VERSION 5.8 ;
BUSBITCHARS "[]" ;
DIVIDERCHAR "/" ;
UNITS
    DATABASE MICRONS 1000 ;
END UNITS

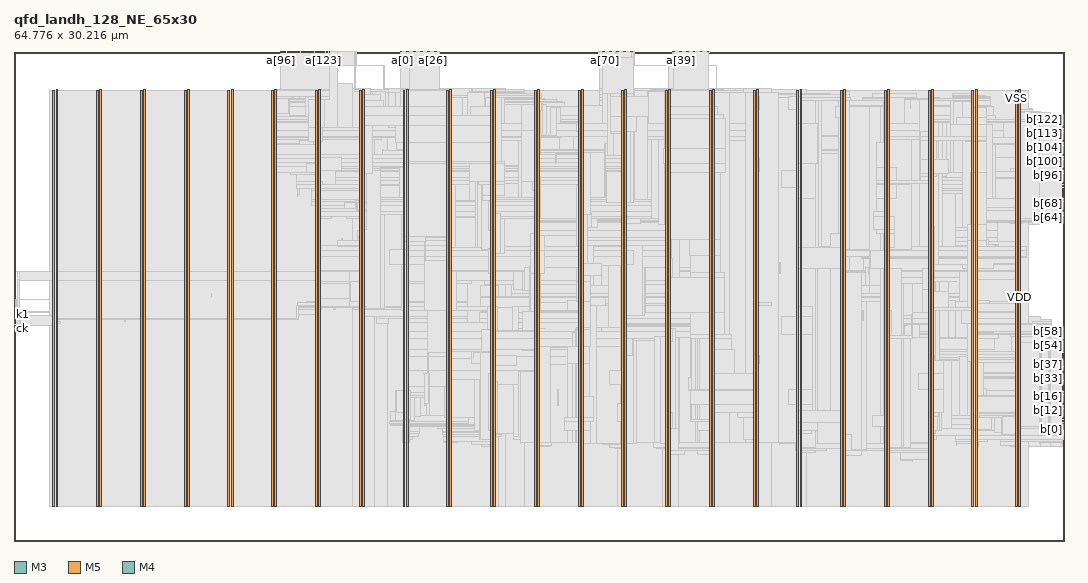
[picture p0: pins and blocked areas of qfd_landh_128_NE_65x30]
MACRO qfd_landh_128_NE_65x30
  FOREIGN qfd_landh_128_NE_65x30 0 0 ;
  CLASS BLOCK ;
  SIZE 64.776 BY 30.216 ;
  PIN a[0]
    DIRECTION INPUT ;
    USE SIGNAL ;
    PORT
      LAYER M3 ;
        RECT  23.94 30.179 23.958 30.216 ;
    END
  END a[0]
  PIN a[100]
    DIRECTION INPUT ;
    USE SIGNAL ;
    PORT
      LAYER M5 ;
        RECT  16.848 30.132 16.872 30.216 ;
    END
  END a[100]
  PIN a[101]
    DIRECTION INPUT ;
    USE SIGNAL ;
    PORT
      LAYER M5 ;
        RECT  16.944 30.132 16.968 30.216 ;
    END
  END a[101]
  PIN a[102]
    DIRECTION INPUT ;
    USE SIGNAL ;
    PORT
      LAYER M5 ;
        RECT  17.04 30.132 17.064 30.216 ;
    END
  END a[102]
  PIN a[103]
    DIRECTION INPUT ;
    USE SIGNAL ;
    PORT
      LAYER M5 ;
        RECT  17.136 30.132 17.16 30.216 ;
    END
  END a[103]
  PIN a[104]
    DIRECTION INPUT ;
    USE SIGNAL ;
    PORT
      LAYER M5 ;
        RECT  17.232 30.132 17.256 30.216 ;
    END
  END a[104]
  PIN a[105]
    DIRECTION INPUT ;
    USE SIGNAL ;
    PORT
      LAYER M5 ;
        RECT  17.328 30.132 17.352 30.216 ;
    END
  END a[105]
  PIN a[106]
    DIRECTION INPUT ;
    USE SIGNAL ;
    PORT
      LAYER M5 ;
        RECT  17.424 30.132 17.448 30.216 ;
    END
  END a[106]
  PIN a[107]
    DIRECTION INPUT ;
    USE SIGNAL ;
    PORT
      LAYER M5 ;
        RECT  17.52 30.132 17.544 30.216 ;
    END
  END a[107]
  PIN a[108]
    DIRECTION INPUT ;
    USE SIGNAL ;
    PORT
      LAYER M5 ;
        RECT  17.616 30.132 17.64 30.216 ;
    END
  END a[108]
  PIN a[109]
    DIRECTION INPUT ;
    USE SIGNAL ;
    PORT
      LAYER M5 ;
        RECT  17.712 30.132 17.736 30.216 ;
    END
  END a[109]
  PIN a[10]
    DIRECTION INPUT ;
    USE SIGNAL ;
    PORT
      LAYER M3 ;
        RECT  24.66 30.179 24.678 30.216 ;
    END
  END a[10]
  PIN a[110]
    DIRECTION INPUT ;
    USE SIGNAL ;
    PORT
      LAYER M5 ;
        RECT  17.808 30.132 17.832 30.216 ;
    END
  END a[110]
  PIN a[111]
    DIRECTION INPUT ;
    USE SIGNAL ;
    PORT
      LAYER M5 ;
        RECT  17.904 30.132 17.928 30.216 ;
    END
  END a[111]
  PIN a[112]
    DIRECTION INPUT ;
    USE SIGNAL ;
    PORT
      LAYER M5 ;
        RECT  18 30.132 18.024 30.216 ;
    END
  END a[112]
  PIN a[113]
    DIRECTION INPUT ;
    USE SIGNAL ;
    PORT
      LAYER M5 ;
        RECT  18.096 30.132 18.12 30.216 ;
    END
  END a[113]
  PIN a[114]
    DIRECTION INPUT ;
    USE SIGNAL ;
    PORT
      LAYER M5 ;
        RECT  18.192 30.132 18.216 30.216 ;
    END
  END a[114]
  PIN a[115]
    DIRECTION INPUT ;
    USE SIGNAL ;
    PORT
      LAYER M5 ;
        RECT  18.288 30.132 18.312 30.216 ;
    END
  END a[115]
  PIN a[116]
    DIRECTION INPUT ;
    USE SIGNAL ;
    PORT
      LAYER M5 ;
        RECT  18.384 30.132 18.408 30.216 ;
    END
  END a[116]
  PIN a[117]
    DIRECTION INPUT ;
    USE SIGNAL ;
    PORT
      LAYER M5 ;
        RECT  18.48 30.132 18.504 30.216 ;
    END
  END a[117]
  PIN a[118]
    DIRECTION INPUT ;
    USE SIGNAL ;
    PORT
      LAYER M5 ;
        RECT  18.576 30.132 18.6 30.216 ;
    END
  END a[118]
  PIN a[119]
    DIRECTION INPUT ;
    USE SIGNAL ;
    PORT
      LAYER M5 ;
        RECT  18.672 30.132 18.696 30.216 ;
    END
  END a[119]
  PIN a[11]
    DIRECTION INPUT ;
    USE SIGNAL ;
    PORT
      LAYER M3 ;
        RECT  24.732 30.179 24.75 30.216 ;
    END
  END a[11]
  PIN a[120]
    DIRECTION INPUT ;
    USE SIGNAL ;
    PORT
      LAYER M5 ;
        RECT  18.768 30.132 18.792 30.216 ;
    END
  END a[120]
  PIN a[121]
    DIRECTION INPUT ;
    USE SIGNAL ;
    PORT
      LAYER M5 ;
        RECT  18.864 30.132 18.888 30.216 ;
    END
  END a[121]
  PIN a[122]
    DIRECTION INPUT ;
    USE SIGNAL ;
    PORT
      LAYER M5 ;
        RECT  18.96 30.132 18.984 30.216 ;
    END
  END a[122]
  PIN a[123]
    DIRECTION INPUT ;
    USE SIGNAL ;
    PORT
      LAYER M5 ;
        RECT  19.056 30.132 19.08 30.216 ;
    END
  END a[123]
  PIN a[124]
    DIRECTION INPUT ;
    USE SIGNAL ;
    PORT
      LAYER M5 ;
        RECT  19.152 30.132 19.176 30.216 ;
    END
  END a[124]
  PIN a[125]
    DIRECTION INPUT ;
    USE SIGNAL ;
    PORT
      LAYER M5 ;
        RECT  19.248 30.132 19.272 30.216 ;
    END
  END a[125]
  PIN a[126]
    DIRECTION INPUT ;
    USE SIGNAL ;
    PORT
      LAYER M5 ;
        RECT  19.344 30.132 19.368 30.216 ;
    END
  END a[126]
  PIN a[127]
    DIRECTION INPUT ;
    USE SIGNAL ;
    PORT
      LAYER M5 ;
        RECT  19.44 30.132 19.464 30.216 ;
    END
  END a[127]
  PIN a[12]
    DIRECTION INPUT ;
    USE SIGNAL ;
    PORT
      LAYER M3 ;
        RECT  24.804 30.179 24.822 30.216 ;
    END
  END a[12]
  PIN a[13]
    DIRECTION INPUT ;
    USE SIGNAL ;
    PORT
      LAYER M3 ;
        RECT  24.876 30.179 24.894 30.216 ;
    END
  END a[13]
  PIN a[14]
    DIRECTION INPUT ;
    USE SIGNAL ;
    PORT
      LAYER M3 ;
        RECT  24.948 30.179 24.966 30.216 ;
    END
  END a[14]
  PIN a[15]
    DIRECTION INPUT ;
    USE SIGNAL ;
    PORT
      LAYER M3 ;
        RECT  25.02 30.179 25.038 30.216 ;
    END
  END a[15]
  PIN a[16]
    DIRECTION INPUT ;
    USE SIGNAL ;
    PORT
      LAYER M3 ;
        RECT  25.092 30.179 25.11 30.216 ;
    END
  END a[16]
  PIN a[17]
    DIRECTION INPUT ;
    USE SIGNAL ;
    PORT
      LAYER M3 ;
        RECT  25.164 30.179 25.182 30.216 ;
    END
  END a[17]
  PIN a[18]
    DIRECTION INPUT ;
    USE SIGNAL ;
    PORT
      LAYER M3 ;
        RECT  25.236 30.179 25.254 30.216 ;
    END
  END a[18]
  PIN a[19]
    DIRECTION INPUT ;
    USE SIGNAL ;
    PORT
      LAYER M3 ;
        RECT  25.308 30.179 25.326 30.216 ;
    END
  END a[19]
  PIN a[1]
    DIRECTION INPUT ;
    USE SIGNAL ;
    PORT
      LAYER M3 ;
        RECT  24.012 30.179 24.03 30.216 ;
    END
  END a[1]
  PIN a[20]
    DIRECTION INPUT ;
    USE SIGNAL ;
    PORT
      LAYER M3 ;
        RECT  25.38 30.179 25.398 30.216 ;
    END
  END a[20]
  PIN a[21]
    DIRECTION INPUT ;
    USE SIGNAL ;
    PORT
      LAYER M3 ;
        RECT  25.452 30.179 25.47 30.216 ;
    END
  END a[21]
  PIN a[22]
    DIRECTION INPUT ;
    USE SIGNAL ;
    PORT
      LAYER M3 ;
        RECT  25.524 30.179 25.542 30.216 ;
    END
  END a[22]
  PIN a[23]
    DIRECTION INPUT ;
    USE SIGNAL ;
    PORT
      LAYER M3 ;
        RECT  25.596 30.179 25.614 30.216 ;
    END
  END a[23]
  PIN a[24]
    DIRECTION INPUT ;
    USE SIGNAL ;
    PORT
      LAYER M3 ;
        RECT  25.668 30.179 25.686 30.216 ;
    END
  END a[24]
  PIN a[25]
    DIRECTION INPUT ;
    USE SIGNAL ;
    PORT
      LAYER M3 ;
        RECT  25.74 30.179 25.758 30.216 ;
    END
  END a[25]
  PIN a[26]
    DIRECTION INPUT ;
    USE SIGNAL ;
    PORT
      LAYER M3 ;
        RECT  25.812 30.179 25.83 30.216 ;
    END
  END a[26]
  PIN a[27]
    DIRECTION INPUT ;
    USE SIGNAL ;
    PORT
      LAYER M3 ;
        RECT  25.884 30.179 25.902 30.216 ;
    END
  END a[27]
  PIN a[28]
    DIRECTION INPUT ;
    USE SIGNAL ;
    PORT
      LAYER M3 ;
        RECT  25.956 30.179 25.974 30.216 ;
    END
  END a[28]
  PIN a[29]
    DIRECTION INPUT ;
    USE SIGNAL ;
    PORT
      LAYER M3 ;
        RECT  26.028 30.179 26.046 30.216 ;
    END
  END a[29]
  PIN a[2]
    DIRECTION INPUT ;
    USE SIGNAL ;
    PORT
      LAYER M3 ;
        RECT  24.084 30.179 24.102 30.216 ;
    END
  END a[2]
  PIN a[30]
    DIRECTION INPUT ;
    USE SIGNAL ;
    PORT
      LAYER M3 ;
        RECT  26.1 30.179 26.118 30.216 ;
    END
  END a[30]
  PIN a[31]
    DIRECTION INPUT ;
    USE SIGNAL ;
    PORT
      LAYER M3 ;
        RECT  26.172 30.179 26.19 30.216 ;
    END
  END a[31]
  PIN a[32]
    DIRECTION INPUT ;
    USE SIGNAL ;
    PORT
      LAYER M3 ;
        RECT  40.644 30.179 40.662 30.216 ;
    END
  END a[32]
  PIN a[33]
    DIRECTION INPUT ;
    USE SIGNAL ;
    PORT
      LAYER M3 ;
        RECT  40.716 30.179 40.734 30.216 ;
    END
  END a[33]
  PIN a[34]
    DIRECTION INPUT ;
    USE SIGNAL ;
    PORT
      LAYER M3 ;
        RECT  40.788 30.179 40.806 30.216 ;
    END
  END a[34]
  PIN a[35]
    DIRECTION INPUT ;
    USE SIGNAL ;
    PORT
      LAYER M3 ;
        RECT  40.86 30.179 40.878 30.216 ;
    END
  END a[35]
  PIN a[36]
    DIRECTION INPUT ;
    USE SIGNAL ;
    PORT
      LAYER M3 ;
        RECT  40.932 30.179 40.95 30.216 ;
    END
  END a[36]
  PIN a[37]
    DIRECTION INPUT ;
    USE SIGNAL ;
    PORT
      LAYER M3 ;
        RECT  41.004 30.179 41.022 30.216 ;
    END
  END a[37]
  PIN a[38]
    DIRECTION INPUT ;
    USE SIGNAL ;
    PORT
      LAYER M3 ;
        RECT  41.076 30.179 41.094 30.216 ;
    END
  END a[38]
  PIN a[39]
    DIRECTION INPUT ;
    USE SIGNAL ;
    PORT
      LAYER M3 ;
        RECT  41.148 30.179 41.166 30.216 ;
    END
  END a[39]
  PIN a[3]
    DIRECTION INPUT ;
    USE SIGNAL ;
    PORT
      LAYER M3 ;
        RECT  24.156 30.179 24.174 30.216 ;
    END
  END a[3]
  PIN a[40]
    DIRECTION INPUT ;
    USE SIGNAL ;
    PORT
      LAYER M3 ;
        RECT  41.22 30.179 41.238 30.216 ;
    END
  END a[40]
  PIN a[41]
    DIRECTION INPUT ;
    USE SIGNAL ;
    PORT
      LAYER M3 ;
        RECT  41.292 30.179 41.31 30.216 ;
    END
  END a[41]
  PIN a[42]
    DIRECTION INPUT ;
    USE SIGNAL ;
    PORT
      LAYER M3 ;
        RECT  41.364 30.179 41.382 30.216 ;
    END
  END a[42]
  PIN a[43]
    DIRECTION INPUT ;
    USE SIGNAL ;
    PORT
      LAYER M3 ;
        RECT  41.436 30.179 41.454 30.216 ;
    END
  END a[43]
  PIN a[44]
    DIRECTION INPUT ;
    USE SIGNAL ;
    PORT
      LAYER M3 ;
        RECT  41.508 30.179 41.526 30.216 ;
    END
  END a[44]
  PIN a[45]
    DIRECTION INPUT ;
    USE SIGNAL ;
    PORT
      LAYER M3 ;
        RECT  41.58 30.179 41.598 30.216 ;
    END
  END a[45]
  PIN a[46]
    DIRECTION INPUT ;
    USE SIGNAL ;
    PORT
      LAYER M3 ;
        RECT  41.652 30.179 41.67 30.216 ;
    END
  END a[46]
  PIN a[47]
    DIRECTION INPUT ;
    USE SIGNAL ;
    PORT
      LAYER M3 ;
        RECT  41.724 30.179 41.742 30.216 ;
    END
  END a[47]
  PIN a[48]
    DIRECTION INPUT ;
    USE SIGNAL ;
    PORT
      LAYER M3 ;
        RECT  41.796 30.179 41.814 30.216 ;
    END
  END a[48]
  PIN a[49]
    DIRECTION INPUT ;
    USE SIGNAL ;
    PORT
      LAYER M3 ;
        RECT  41.868 30.179 41.886 30.216 ;
    END
  END a[49]
  PIN a[4]
    DIRECTION INPUT ;
    USE SIGNAL ;
    PORT
      LAYER M3 ;
        RECT  24.228 30.179 24.246 30.216 ;
    END
  END a[4]
  PIN a[50]
    DIRECTION INPUT ;
    USE SIGNAL ;
    PORT
      LAYER M3 ;
        RECT  41.94 30.179 41.958 30.216 ;
    END
  END a[50]
  PIN a[51]
    DIRECTION INPUT ;
    USE SIGNAL ;
    PORT
      LAYER M3 ;
        RECT  42.012 30.179 42.03 30.216 ;
    END
  END a[51]
  PIN a[52]
    DIRECTION INPUT ;
    USE SIGNAL ;
    PORT
      LAYER M3 ;
        RECT  42.084 30.179 42.102 30.216 ;
    END
  END a[52]
  PIN a[53]
    DIRECTION INPUT ;
    USE SIGNAL ;
    PORT
      LAYER M3 ;
        RECT  42.156 30.179 42.174 30.216 ;
    END
  END a[53]
  PIN a[54]
    DIRECTION INPUT ;
    USE SIGNAL ;
    PORT
      LAYER M3 ;
        RECT  42.228 30.179 42.246 30.216 ;
    END
  END a[54]
  PIN a[55]
    DIRECTION INPUT ;
    USE SIGNAL ;
    PORT
      LAYER M3 ;
        RECT  42.3 30.179 42.318 30.216 ;
    END
  END a[55]
  PIN a[56]
    DIRECTION INPUT ;
    USE SIGNAL ;
    PORT
      LAYER M3 ;
        RECT  42.372 30.179 42.39 30.216 ;
    END
  END a[56]
  PIN a[57]
    DIRECTION INPUT ;
    USE SIGNAL ;
    PORT
      LAYER M3 ;
        RECT  42.444 30.179 42.462 30.216 ;
    END
  END a[57]
  PIN a[58]
    DIRECTION INPUT ;
    USE SIGNAL ;
    PORT
      LAYER M3 ;
        RECT  42.516 30.179 42.534 30.216 ;
    END
  END a[58]
  PIN a[59]
    DIRECTION INPUT ;
    USE SIGNAL ;
    PORT
      LAYER M3 ;
        RECT  42.588 30.179 42.606 30.216 ;
    END
  END a[59]
  PIN a[5]
    DIRECTION INPUT ;
    USE SIGNAL ;
    PORT
      LAYER M3 ;
        RECT  24.3 30.179 24.318 30.216 ;
    END
  END a[5]
  PIN a[60]
    DIRECTION INPUT ;
    USE SIGNAL ;
    PORT
      LAYER M3 ;
        RECT  42.66 30.179 42.678 30.216 ;
    END
  END a[60]
  PIN a[61]
    DIRECTION INPUT ;
    USE SIGNAL ;
    PORT
      LAYER M3 ;
        RECT  42.732 30.179 42.75 30.216 ;
    END
  END a[61]
  PIN a[62]
    DIRECTION INPUT ;
    USE SIGNAL ;
    PORT
      LAYER M3 ;
        RECT  42.804 30.179 42.822 30.216 ;
    END
  END a[62]
  PIN a[63]
    DIRECTION INPUT ;
    USE SIGNAL ;
    PORT
      LAYER M3 ;
        RECT  42.876 30.179 42.894 30.216 ;
    END
  END a[63]
  PIN a[64]
    DIRECTION INPUT ;
    USE SIGNAL ;
    PORT
      LAYER M3 ;
        RECT  36.036 30.179 36.054 30.216 ;
    END
  END a[64]
  PIN a[65]
    DIRECTION INPUT ;
    USE SIGNAL ;
    PORT
      LAYER M3 ;
        RECT  36.108 30.179 36.126 30.216 ;
    END
  END a[65]
  PIN a[66]
    DIRECTION INPUT ;
    USE SIGNAL ;
    PORT
      LAYER M3 ;
        RECT  36.18 30.179 36.198 30.216 ;
    END
  END a[66]
  PIN a[67]
    DIRECTION INPUT ;
    USE SIGNAL ;
    PORT
      LAYER M3 ;
        RECT  36.252 30.179 36.27 30.216 ;
    END
  END a[67]
  PIN a[68]
    DIRECTION INPUT ;
    USE SIGNAL ;
    PORT
      LAYER M3 ;
        RECT  36.324 30.179 36.342 30.216 ;
    END
  END a[68]
  PIN a[69]
    DIRECTION INPUT ;
    USE SIGNAL ;
    PORT
      LAYER M3 ;
        RECT  36.396 30.179 36.414 30.216 ;
    END
  END a[69]
  PIN a[6]
    DIRECTION INPUT ;
    USE SIGNAL ;
    PORT
      LAYER M3 ;
        RECT  24.372 30.179 24.39 30.216 ;
    END
  END a[6]
  PIN a[70]
    DIRECTION INPUT ;
    USE SIGNAL ;
    PORT
      LAYER M3 ;
        RECT  36.468 30.179 36.486 30.216 ;
    END
  END a[70]
  PIN a[71]
    DIRECTION INPUT ;
    USE SIGNAL ;
    PORT
      LAYER M3 ;
        RECT  36.54 30.179 36.558 30.216 ;
    END
  END a[71]
  PIN a[72]
    DIRECTION INPUT ;
    USE SIGNAL ;
    PORT
      LAYER M3 ;
        RECT  36.612 30.179 36.63 30.216 ;
    END
  END a[72]
  PIN a[73]
    DIRECTION INPUT ;
    USE SIGNAL ;
    PORT
      LAYER M3 ;
        RECT  36.684 30.179 36.702 30.216 ;
    END
  END a[73]
  PIN a[74]
    DIRECTION INPUT ;
    USE SIGNAL ;
    PORT
      LAYER M3 ;
        RECT  36.756 30.179 36.774 30.216 ;
    END
  END a[74]
  PIN a[75]
    DIRECTION INPUT ;
    USE SIGNAL ;
    PORT
      LAYER M3 ;
        RECT  36.828 30.179 36.846 30.216 ;
    END
  END a[75]
  PIN a[76]
    DIRECTION INPUT ;
    USE SIGNAL ;
    PORT
      LAYER M3 ;
        RECT  36.9 30.179 36.918 30.216 ;
    END
  END a[76]
  PIN a[77]
    DIRECTION INPUT ;
    USE SIGNAL ;
    PORT
      LAYER M3 ;
        RECT  36.972 30.179 36.99 30.216 ;
    END
  END a[77]
  PIN a[78]
    DIRECTION INPUT ;
    USE SIGNAL ;
    PORT
      LAYER M3 ;
        RECT  37.044 30.179 37.062 30.216 ;
    END
  END a[78]
  PIN a[79]
    DIRECTION INPUT ;
    USE SIGNAL ;
    PORT
      LAYER M3 ;
        RECT  37.116 30.179 37.134 30.216 ;
    END
  END a[79]
  PIN a[7]
    DIRECTION INPUT ;
    USE SIGNAL ;
    PORT
      LAYER M3 ;
        RECT  24.444 30.179 24.462 30.216 ;
    END
  END a[7]
  PIN a[80]
    DIRECTION INPUT ;
    USE SIGNAL ;
    PORT
      LAYER M3 ;
        RECT  37.188 30.179 37.206 30.216 ;
    END
  END a[80]
  PIN a[81]
    DIRECTION INPUT ;
    USE SIGNAL ;
    PORT
      LAYER M3 ;
        RECT  37.26 30.179 37.278 30.216 ;
    END
  END a[81]
  PIN a[82]
    DIRECTION INPUT ;
    USE SIGNAL ;
    PORT
      LAYER M3 ;
        RECT  37.332 30.179 37.35 30.216 ;
    END
  END a[82]
  PIN a[83]
    DIRECTION INPUT ;
    USE SIGNAL ;
    PORT
      LAYER M3 ;
        RECT  37.404 30.179 37.422 30.216 ;
    END
  END a[83]
  PIN a[84]
    DIRECTION INPUT ;
    USE SIGNAL ;
    PORT
      LAYER M3 ;
        RECT  37.476 30.179 37.494 30.216 ;
    END
  END a[84]
  PIN a[85]
    DIRECTION INPUT ;
    USE SIGNAL ;
    PORT
      LAYER M3 ;
        RECT  37.548 30.179 37.566 30.216 ;
    END
  END a[85]
  PIN a[86]
    DIRECTION INPUT ;
    USE SIGNAL ;
    PORT
      LAYER M3 ;
        RECT  37.62 30.179 37.638 30.216 ;
    END
  END a[86]
  PIN a[87]
    DIRECTION INPUT ;
    USE SIGNAL ;
    PORT
      LAYER M3 ;
        RECT  37.692 30.179 37.71 30.216 ;
    END
  END a[87]
  PIN a[88]
    DIRECTION INPUT ;
    USE SIGNAL ;
    PORT
      LAYER M3 ;
        RECT  37.764 30.179 37.782 30.216 ;
    END
  END a[88]
  PIN a[89]
    DIRECTION INPUT ;
    USE SIGNAL ;
    PORT
      LAYER M3 ;
        RECT  37.836 30.179 37.854 30.216 ;
    END
  END a[89]
  PIN a[8]
    DIRECTION INPUT ;
    USE SIGNAL ;
    PORT
      LAYER M3 ;
        RECT  24.516 30.179 24.534 30.216 ;
    END
  END a[8]
  PIN a[90]
    DIRECTION INPUT ;
    USE SIGNAL ;
    PORT
      LAYER M3 ;
        RECT  37.908 30.179 37.926 30.216 ;
    END
  END a[90]
  PIN a[91]
    DIRECTION INPUT ;
    USE SIGNAL ;
    PORT
      LAYER M3 ;
        RECT  37.98 30.179 37.998 30.216 ;
    END
  END a[91]
  PIN a[92]
    DIRECTION INPUT ;
    USE SIGNAL ;
    PORT
      LAYER M3 ;
        RECT  38.052 30.179 38.07 30.216 ;
    END
  END a[92]
  PIN a[93]
    DIRECTION INPUT ;
    USE SIGNAL ;
    PORT
      LAYER M3 ;
        RECT  38.124 30.179 38.142 30.216 ;
    END
  END a[93]
  PIN a[94]
    DIRECTION INPUT ;
    USE SIGNAL ;
    PORT
      LAYER M3 ;
        RECT  38.196 30.179 38.214 30.216 ;
    END
  END a[94]
  PIN a[95]
    DIRECTION INPUT ;
    USE SIGNAL ;
    PORT
      LAYER M3 ;
        RECT  38.268 30.179 38.286 30.216 ;
    END
  END a[95]
  PIN a[96]
    DIRECTION INPUT ;
    USE SIGNAL ;
    PORT
      LAYER M5 ;
        RECT  16.464 30.132 16.488 30.216 ;
    END
  END a[96]
  PIN a[97]
    DIRECTION INPUT ;
    USE SIGNAL ;
    PORT
      LAYER M5 ;
        RECT  16.56 30.132 16.584 30.216 ;
    END
  END a[97]
  PIN a[98]
    DIRECTION INPUT ;
    USE SIGNAL ;
    PORT
      LAYER M5 ;
        RECT  16.656 30.132 16.68 30.216 ;
    END
  END a[98]
  PIN a[99]
    DIRECTION INPUT ;
    USE SIGNAL ;
    PORT
      LAYER M5 ;
        RECT  16.752 30.132 16.776 30.216 ;
    END
  END a[99]
  PIN a[9]
    DIRECTION INPUT ;
    USE SIGNAL ;
    PORT
      LAYER M3 ;
        RECT  24.588 30.179 24.606 30.216 ;
    END
  END a[9]
  PIN b[0]
    DIRECTION OUTPUT ;
    USE SIGNAL ;
    PORT
      LAYER M4 ;
        RECT  64.692 6.864 64.776 6.888 ;
    END
  END b[0]
  PIN b[100]
    DIRECTION OUTPUT ;
    USE SIGNAL ;
    PORT
      LAYER M4 ;
        RECT  64.692 23.376 64.776 23.4 ;
    END
  END b[100]
  PIN b[101]
    DIRECTION OUTPUT ;
    USE SIGNAL ;
    PORT
      LAYER M4 ;
        RECT  64.692 23.472 64.776 23.496 ;
    END
  END b[101]
  PIN b[102]
    DIRECTION OUTPUT ;
    USE SIGNAL ;
    PORT
      LAYER M4 ;
        RECT  64.692 23.568 64.776 23.592 ;
    END
  END b[102]
  PIN b[103]
    DIRECTION OUTPUT ;
    USE SIGNAL ;
    PORT
      LAYER M4 ;
        RECT  64.692 23.664 64.776 23.688 ;
    END
  END b[103]
  PIN b[104]
    DIRECTION OUTPUT ;
    USE SIGNAL ;
    PORT
      LAYER M4 ;
        RECT  64.692 23.76 64.776 23.784 ;
    END
  END b[104]
  PIN b[105]
    DIRECTION OUTPUT ;
    USE SIGNAL ;
    PORT
      LAYER M4 ;
        RECT  64.692 23.856 64.776 23.88 ;
    END
  END b[105]
  PIN b[106]
    DIRECTION OUTPUT ;
    USE SIGNAL ;
    PORT
      LAYER M4 ;
        RECT  64.692 23.952 64.776 23.976 ;
    END
  END b[106]
  PIN b[107]
    DIRECTION OUTPUT ;
    USE SIGNAL ;
    PORT
      LAYER M4 ;
        RECT  64.692 24.048 64.776 24.072 ;
    END
  END b[107]
  PIN b[108]
    DIRECTION OUTPUT ;
    USE SIGNAL ;
    PORT
      LAYER M4 ;
        RECT  64.692 24.144 64.776 24.168 ;
    END
  END b[108]
  PIN b[109]
    DIRECTION OUTPUT ;
    USE SIGNAL ;
    PORT
      LAYER M4 ;
        RECT  64.692 24.24 64.776 24.264 ;
    END
  END b[109]
  PIN b[10]
    DIRECTION OUTPUT ;
    USE SIGNAL ;
    PORT
      LAYER M4 ;
        RECT  64.692 7.824 64.776 7.848 ;
    END
  END b[10]
  PIN b[110]
    DIRECTION OUTPUT ;
    USE SIGNAL ;
    PORT
      LAYER M4 ;
        RECT  64.692 24.336 64.776 24.36 ;
    END
  END b[110]
  PIN b[111]
    DIRECTION OUTPUT ;
    USE SIGNAL ;
    PORT
      LAYER M4 ;
        RECT  64.692 24.432 64.776 24.456 ;
    END
  END b[111]
  PIN b[112]
    DIRECTION OUTPUT ;
    USE SIGNAL ;
    PORT
      LAYER M4 ;
        RECT  64.692 24.528 64.776 24.552 ;
    END
  END b[112]
  PIN b[113]
    DIRECTION OUTPUT ;
    USE SIGNAL ;
    PORT
      LAYER M4 ;
        RECT  64.692 24.624 64.776 24.648 ;
    END
  END b[113]
  PIN b[114]
    DIRECTION OUTPUT ;
    USE SIGNAL ;
    PORT
      LAYER M4 ;
        RECT  64.692 24.72 64.776 24.744 ;
    END
  END b[114]
  PIN b[115]
    DIRECTION OUTPUT ;
    USE SIGNAL ;
    PORT
      LAYER M4 ;
        RECT  64.692 24.816 64.776 24.84 ;
    END
  END b[115]
  PIN b[116]
    DIRECTION OUTPUT ;
    USE SIGNAL ;
    PORT
      LAYER M4 ;
        RECT  64.692 24.912 64.776 24.936 ;
    END
  END b[116]
  PIN b[117]
    DIRECTION OUTPUT ;
    USE SIGNAL ;
    PORT
      LAYER M4 ;
        RECT  64.692 25.008 64.776 25.032 ;
    END
  END b[117]
  PIN b[118]
    DIRECTION OUTPUT ;
    USE SIGNAL ;
    PORT
      LAYER M4 ;
        RECT  64.692 25.104 64.776 25.128 ;
    END
  END b[118]
  PIN b[119]
    DIRECTION OUTPUT ;
    USE SIGNAL ;
    PORT
      LAYER M4 ;
        RECT  64.692 25.2 64.776 25.224 ;
    END
  END b[119]
  PIN b[11]
    DIRECTION OUTPUT ;
    USE SIGNAL ;
    PORT
      LAYER M4 ;
        RECT  64.692 7.92 64.776 7.944 ;
    END
  END b[11]
  PIN b[120]
    DIRECTION OUTPUT ;
    USE SIGNAL ;
    PORT
      LAYER M4 ;
        RECT  64.692 25.296 64.776 25.32 ;
    END
  END b[120]
  PIN b[121]
    DIRECTION OUTPUT ;
    USE SIGNAL ;
    PORT
      LAYER M4 ;
        RECT  64.692 25.392 64.776 25.416 ;
    END
  END b[121]
  PIN b[122]
    DIRECTION OUTPUT ;
    USE SIGNAL ;
    PORT
      LAYER M4 ;
        RECT  64.692 25.488 64.776 25.512 ;
    END
  END b[122]
  PIN b[123]
    DIRECTION OUTPUT ;
    USE SIGNAL ;
    PORT
      LAYER M4 ;
        RECT  64.692 25.584 64.776 25.608 ;
    END
  END b[123]
  PIN b[124]
    DIRECTION OUTPUT ;
    USE SIGNAL ;
    PORT
      LAYER M4 ;
        RECT  64.692 25.68 64.776 25.704 ;
    END
  END b[124]
  PIN b[125]
    DIRECTION OUTPUT ;
    USE SIGNAL ;
    PORT
      LAYER M4 ;
        RECT  64.692 25.776 64.776 25.8 ;
    END
  END b[125]
  PIN b[126]
    DIRECTION OUTPUT ;
    USE SIGNAL ;
    PORT
      LAYER M4 ;
        RECT  64.692 25.872 64.776 25.896 ;
    END
  END b[126]
  PIN b[127]
    DIRECTION OUTPUT ;
    USE SIGNAL ;
    PORT
      LAYER M4 ;
        RECT  64.692 25.968 64.776 25.992 ;
    END
  END b[127]
  PIN b[12]
    DIRECTION OUTPUT ;
    USE SIGNAL ;
    PORT
      LAYER M4 ;
        RECT  64.692 8.016 64.776 8.04 ;
    END
  END b[12]
  PIN b[13]
    DIRECTION OUTPUT ;
    USE SIGNAL ;
    PORT
      LAYER M4 ;
        RECT  64.692 8.112 64.776 8.136 ;
    END
  END b[13]
  PIN b[14]
    DIRECTION OUTPUT ;
    USE SIGNAL ;
    PORT
      LAYER M4 ;
        RECT  64.692 8.208 64.776 8.232 ;
    END
  END b[14]
  PIN b[15]
    DIRECTION OUTPUT ;
    USE SIGNAL ;
    PORT
      LAYER M4 ;
        RECT  64.692 8.304 64.776 8.328 ;
    END
  END b[15]
  PIN b[16]
    DIRECTION OUTPUT ;
    USE SIGNAL ;
    PORT
      LAYER M4 ;
        RECT  64.692 8.4 64.776 8.424 ;
    END
  END b[16]
  PIN b[17]
    DIRECTION OUTPUT ;
    USE SIGNAL ;
    PORT
      LAYER M4 ;
        RECT  64.692 8.496 64.776 8.52 ;
    END
  END b[17]
  PIN b[18]
    DIRECTION OUTPUT ;
    USE SIGNAL ;
    PORT
      LAYER M4 ;
        RECT  64.692 8.592 64.776 8.616 ;
    END
  END b[18]
  PIN b[19]
    DIRECTION OUTPUT ;
    USE SIGNAL ;
    PORT
      LAYER M4 ;
        RECT  64.692 8.688 64.776 8.712 ;
    END
  END b[19]
  PIN b[1]
    DIRECTION OUTPUT ;
    USE SIGNAL ;
    PORT
      LAYER M4 ;
        RECT  64.692 6.96 64.776 6.984 ;
    END
  END b[1]
  PIN b[20]
    DIRECTION OUTPUT ;
    USE SIGNAL ;
    PORT
      LAYER M4 ;
        RECT  64.692 8.784 64.776 8.808 ;
    END
  END b[20]
  PIN b[21]
    DIRECTION OUTPUT ;
    USE SIGNAL ;
    PORT
      LAYER M4 ;
        RECT  64.692 8.88 64.776 8.904 ;
    END
  END b[21]
  PIN b[22]
    DIRECTION OUTPUT ;
    USE SIGNAL ;
    PORT
      LAYER M4 ;
        RECT  64.692 8.976 64.776 9 ;
    END
  END b[22]
  PIN b[23]
    DIRECTION OUTPUT ;
    USE SIGNAL ;
    PORT
      LAYER M4 ;
        RECT  64.692 9.072 64.776 9.096 ;
    END
  END b[23]
  PIN b[24]
    DIRECTION OUTPUT ;
    USE SIGNAL ;
    PORT
      LAYER M4 ;
        RECT  64.692 9.168 64.776 9.192 ;
    END
  END b[24]
  PIN b[25]
    DIRECTION OUTPUT ;
    USE SIGNAL ;
    PORT
      LAYER M4 ;
        RECT  64.692 9.264 64.776 9.288 ;
    END
  END b[25]
  PIN b[26]
    DIRECTION OUTPUT ;
    USE SIGNAL ;
    PORT
      LAYER M4 ;
        RECT  64.692 9.36 64.776 9.384 ;
    END
  END b[26]
  PIN b[27]
    DIRECTION OUTPUT ;
    USE SIGNAL ;
    PORT
      LAYER M4 ;
        RECT  64.692 9.456 64.776 9.48 ;
    END
  END b[27]
  PIN b[28]
    DIRECTION OUTPUT ;
    USE SIGNAL ;
    PORT
      LAYER M4 ;
        RECT  64.692 9.552 64.776 9.576 ;
    END
  END b[28]
  PIN b[29]
    DIRECTION OUTPUT ;
    USE SIGNAL ;
    PORT
      LAYER M4 ;
        RECT  64.692 9.648 64.776 9.672 ;
    END
  END b[29]
  PIN b[2]
    DIRECTION OUTPUT ;
    USE SIGNAL ;
    PORT
      LAYER M4 ;
        RECT  64.692 7.056 64.776 7.08 ;
    END
  END b[2]
  PIN b[30]
    DIRECTION OUTPUT ;
    USE SIGNAL ;
    PORT
      LAYER M4 ;
        RECT  64.692 9.744 64.776 9.768 ;
    END
  END b[30]
  PIN b[31]
    DIRECTION OUTPUT ;
    USE SIGNAL ;
    PORT
      LAYER M4 ;
        RECT  64.692 9.84 64.776 9.864 ;
    END
  END b[31]
  PIN b[32]
    DIRECTION OUTPUT ;
    USE SIGNAL ;
    PORT
      LAYER M4 ;
        RECT  64.692 9.936 64.776 9.96 ;
    END
  END b[32]
  PIN b[33]
    DIRECTION OUTPUT ;
    USE SIGNAL ;
    PORT
      LAYER M4 ;
        RECT  64.692 10.032 64.776 10.056 ;
    END
  END b[33]
  PIN b[34]
    DIRECTION OUTPUT ;
    USE SIGNAL ;
    PORT
      LAYER M4 ;
        RECT  64.692 10.128 64.776 10.152 ;
    END
  END b[34]
  PIN b[35]
    DIRECTION OUTPUT ;
    USE SIGNAL ;
    PORT
      LAYER M4 ;
        RECT  64.692 10.224 64.776 10.248 ;
    END
  END b[35]
  PIN b[36]
    DIRECTION OUTPUT ;
    USE SIGNAL ;
    PORT
      LAYER M4 ;
        RECT  64.692 10.32 64.776 10.344 ;
    END
  END b[36]
  PIN b[37]
    DIRECTION OUTPUT ;
    USE SIGNAL ;
    PORT
      LAYER M4 ;
        RECT  64.692 10.416 64.776 10.44 ;
    END
  END b[37]
  PIN b[38]
    DIRECTION OUTPUT ;
    USE SIGNAL ;
    PORT
      LAYER M4 ;
        RECT  64.692 10.512 64.776 10.536 ;
    END
  END b[38]
  PIN b[39]
    DIRECTION OUTPUT ;
    USE SIGNAL ;
    PORT
      LAYER M4 ;
        RECT  64.692 10.608 64.776 10.632 ;
    END
  END b[39]
  PIN b[3]
    DIRECTION OUTPUT ;
    USE SIGNAL ;
    PORT
      LAYER M4 ;
        RECT  64.692 7.152 64.776 7.176 ;
    END
  END b[3]
  PIN b[40]
    DIRECTION OUTPUT ;
    USE SIGNAL ;
    PORT
      LAYER M4 ;
        RECT  64.692 10.704 64.776 10.728 ;
    END
  END b[40]
  PIN b[41]
    DIRECTION OUTPUT ;
    USE SIGNAL ;
    PORT
      LAYER M4 ;
        RECT  64.692 10.8 64.776 10.824 ;
    END
  END b[41]
  PIN b[42]
    DIRECTION OUTPUT ;
    USE SIGNAL ;
    PORT
      LAYER M4 ;
        RECT  64.692 10.896 64.776 10.92 ;
    END
  END b[42]
  PIN b[43]
    DIRECTION OUTPUT ;
    USE SIGNAL ;
    PORT
      LAYER M4 ;
        RECT  64.692 10.992 64.776 11.016 ;
    END
  END b[43]
  PIN b[44]
    DIRECTION OUTPUT ;
    USE SIGNAL ;
    PORT
      LAYER M4 ;
        RECT  64.692 11.088 64.776 11.112 ;
    END
  END b[44]
  PIN b[45]
    DIRECTION OUTPUT ;
    USE SIGNAL ;
    PORT
      LAYER M4 ;
        RECT  64.692 11.184 64.776 11.208 ;
    END
  END b[45]
  PIN b[46]
    DIRECTION OUTPUT ;
    USE SIGNAL ;
    PORT
      LAYER M4 ;
        RECT  64.692 11.28 64.776 11.304 ;
    END
  END b[46]
  PIN b[47]
    DIRECTION OUTPUT ;
    USE SIGNAL ;
    PORT
      LAYER M4 ;
        RECT  64.692 11.376 64.776 11.4 ;
    END
  END b[47]
  PIN b[48]
    DIRECTION OUTPUT ;
    USE SIGNAL ;
    PORT
      LAYER M4 ;
        RECT  64.692 11.472 64.776 11.496 ;
    END
  END b[48]
  PIN b[49]
    DIRECTION OUTPUT ;
    USE SIGNAL ;
    PORT
      LAYER M4 ;
        RECT  64.692 11.568 64.776 11.592 ;
    END
  END b[49]
  PIN b[4]
    DIRECTION OUTPUT ;
    USE SIGNAL ;
    PORT
      LAYER M4 ;
        RECT  64.692 7.248 64.776 7.272 ;
    END
  END b[4]
  PIN b[50]
    DIRECTION OUTPUT ;
    USE SIGNAL ;
    PORT
      LAYER M4 ;
        RECT  64.692 11.664 64.776 11.688 ;
    END
  END b[50]
  PIN b[51]
    DIRECTION OUTPUT ;
    USE SIGNAL ;
    PORT
      LAYER M4 ;
        RECT  64.692 11.76 64.776 11.784 ;
    END
  END b[51]
  PIN b[52]
    DIRECTION OUTPUT ;
    USE SIGNAL ;
    PORT
      LAYER M4 ;
        RECT  64.692 11.856 64.776 11.88 ;
    END
  END b[52]
  PIN b[53]
    DIRECTION OUTPUT ;
    USE SIGNAL ;
    PORT
      LAYER M4 ;
        RECT  64.692 11.952 64.776 11.976 ;
    END
  END b[53]
  PIN b[54]
    DIRECTION OUTPUT ;
    USE SIGNAL ;
    PORT
      LAYER M4 ;
        RECT  64.692 12.048 64.776 12.072 ;
    END
  END b[54]
  PIN b[55]
    DIRECTION OUTPUT ;
    USE SIGNAL ;
    PORT
      LAYER M4 ;
        RECT  64.692 12.144 64.776 12.168 ;
    END
  END b[55]
  PIN b[56]
    DIRECTION OUTPUT ;
    USE SIGNAL ;
    PORT
      LAYER M4 ;
        RECT  64.692 12.24 64.776 12.264 ;
    END
  END b[56]
  PIN b[57]
    DIRECTION OUTPUT ;
    USE SIGNAL ;
    PORT
      LAYER M4 ;
        RECT  64.692 12.336 64.776 12.36 ;
    END
  END b[57]
  PIN b[58]
    DIRECTION OUTPUT ;
    USE SIGNAL ;
    PORT
      LAYER M4 ;
        RECT  64.692 12.432 64.776 12.456 ;
    END
  END b[58]
  PIN b[59]
    DIRECTION OUTPUT ;
    USE SIGNAL ;
    PORT
      LAYER M4 ;
        RECT  64.692 12.528 64.776 12.552 ;
    END
  END b[59]
  PIN b[5]
    DIRECTION OUTPUT ;
    USE SIGNAL ;
    PORT
      LAYER M4 ;
        RECT  64.692 7.344 64.776 7.368 ;
    END
  END b[5]
  PIN b[60]
    DIRECTION OUTPUT ;
    USE SIGNAL ;
    PORT
      LAYER M4 ;
        RECT  64.692 12.624 64.776 12.648 ;
    END
  END b[60]
  PIN b[61]
    DIRECTION OUTPUT ;
    USE SIGNAL ;
    PORT
      LAYER M4 ;
        RECT  64.692 12.72 64.776 12.744 ;
    END
  END b[61]
  PIN b[62]
    DIRECTION OUTPUT ;
    USE SIGNAL ;
    PORT
      LAYER M4 ;
        RECT  64.692 12.816 64.776 12.84 ;
    END
  END b[62]
  PIN b[63]
    DIRECTION OUTPUT ;
    USE SIGNAL ;
    PORT
      LAYER M4 ;
        RECT  64.692 12.912 64.776 12.936 ;
    END
  END b[63]
  PIN b[64]
    DIRECTION OUTPUT ;
    USE SIGNAL ;
    PORT
      LAYER M4 ;
        RECT  64.692 19.92 64.776 19.944 ;
    END
  END b[64]
  PIN b[65]
    DIRECTION OUTPUT ;
    USE SIGNAL ;
    PORT
      LAYER M4 ;
        RECT  64.692 20.016 64.776 20.04 ;
    END
  END b[65]
  PIN b[66]
    DIRECTION OUTPUT ;
    USE SIGNAL ;
    PORT
      LAYER M4 ;
        RECT  64.692 20.112 64.776 20.136 ;
    END
  END b[66]
  PIN b[67]
    DIRECTION OUTPUT ;
    USE SIGNAL ;
    PORT
      LAYER M4 ;
        RECT  64.692 20.208 64.776 20.232 ;
    END
  END b[67]
  PIN b[68]
    DIRECTION OUTPUT ;
    USE SIGNAL ;
    PORT
      LAYER M4 ;
        RECT  64.692 20.304 64.776 20.328 ;
    END
  END b[68]
  PIN b[69]
    DIRECTION OUTPUT ;
    USE SIGNAL ;
    PORT
      LAYER M4 ;
        RECT  64.692 20.4 64.776 20.424 ;
    END
  END b[69]
  PIN b[6]
    DIRECTION OUTPUT ;
    USE SIGNAL ;
    PORT
      LAYER M4 ;
        RECT  64.692 7.44 64.776 7.464 ;
    END
  END b[6]
  PIN b[70]
    DIRECTION OUTPUT ;
    USE SIGNAL ;
    PORT
      LAYER M4 ;
        RECT  64.692 20.496 64.776 20.52 ;
    END
  END b[70]
  PIN b[71]
    DIRECTION OUTPUT ;
    USE SIGNAL ;
    PORT
      LAYER M4 ;
        RECT  64.692 20.592 64.776 20.616 ;
    END
  END b[71]
  PIN b[72]
    DIRECTION OUTPUT ;
    USE SIGNAL ;
    PORT
      LAYER M4 ;
        RECT  64.692 20.688 64.776 20.712 ;
    END
  END b[72]
  PIN b[73]
    DIRECTION OUTPUT ;
    USE SIGNAL ;
    PORT
      LAYER M4 ;
        RECT  64.692 20.784 64.776 20.808 ;
    END
  END b[73]
  PIN b[74]
    DIRECTION OUTPUT ;
    USE SIGNAL ;
    PORT
      LAYER M4 ;
        RECT  64.692 20.88 64.776 20.904 ;
    END
  END b[74]
  PIN b[75]
    DIRECTION OUTPUT ;
    USE SIGNAL ;
    PORT
      LAYER M4 ;
        RECT  64.692 20.976 64.776 21 ;
    END
  END b[75]
  PIN b[76]
    DIRECTION OUTPUT ;
    USE SIGNAL ;
    PORT
      LAYER M4 ;
        RECT  64.692 21.072 64.776 21.096 ;
    END
  END b[76]
  PIN b[77]
    DIRECTION OUTPUT ;
    USE SIGNAL ;
    PORT
      LAYER M4 ;
        RECT  64.692 21.168 64.776 21.192 ;
    END
  END b[77]
  PIN b[78]
    DIRECTION OUTPUT ;
    USE SIGNAL ;
    PORT
      LAYER M4 ;
        RECT  64.692 21.264 64.776 21.288 ;
    END
  END b[78]
  PIN b[79]
    DIRECTION OUTPUT ;
    USE SIGNAL ;
    PORT
      LAYER M4 ;
        RECT  64.692 21.36 64.776 21.384 ;
    END
  END b[79]
  PIN b[7]
    DIRECTION OUTPUT ;
    USE SIGNAL ;
    PORT
      LAYER M4 ;
        RECT  64.692 7.536 64.776 7.56 ;
    END
  END b[7]
  PIN b[80]
    DIRECTION OUTPUT ;
    USE SIGNAL ;
    PORT
      LAYER M4 ;
        RECT  64.692 21.456 64.776 21.48 ;
    END
  END b[80]
  PIN b[81]
    DIRECTION OUTPUT ;
    USE SIGNAL ;
    PORT
      LAYER M4 ;
        RECT  64.692 21.552 64.776 21.576 ;
    END
  END b[81]
  PIN b[82]
    DIRECTION OUTPUT ;
    USE SIGNAL ;
    PORT
      LAYER M4 ;
        RECT  64.692 21.648 64.776 21.672 ;
    END
  END b[82]
  PIN b[83]
    DIRECTION OUTPUT ;
    USE SIGNAL ;
    PORT
      LAYER M4 ;
        RECT  64.692 21.744 64.776 21.768 ;
    END
  END b[83]
  PIN b[84]
    DIRECTION OUTPUT ;
    USE SIGNAL ;
    PORT
      LAYER M4 ;
        RECT  64.692 21.84 64.776 21.864 ;
    END
  END b[84]
  PIN b[85]
    DIRECTION OUTPUT ;
    USE SIGNAL ;
    PORT
      LAYER M4 ;
        RECT  64.692 21.936 64.776 21.96 ;
    END
  END b[85]
  PIN b[86]
    DIRECTION OUTPUT ;
    USE SIGNAL ;
    PORT
      LAYER M4 ;
        RECT  64.692 22.032 64.776 22.056 ;
    END
  END b[86]
  PIN b[87]
    DIRECTION OUTPUT ;
    USE SIGNAL ;
    PORT
      LAYER M4 ;
        RECT  64.692 22.128 64.776 22.152 ;
    END
  END b[87]
  PIN b[88]
    DIRECTION OUTPUT ;
    USE SIGNAL ;
    PORT
      LAYER M4 ;
        RECT  64.692 22.224 64.776 22.248 ;
    END
  END b[88]
  PIN b[89]
    DIRECTION OUTPUT ;
    USE SIGNAL ;
    PORT
      LAYER M4 ;
        RECT  64.692 22.32 64.776 22.344 ;
    END
  END b[89]
  PIN b[8]
    DIRECTION OUTPUT ;
    USE SIGNAL ;
    PORT
      LAYER M4 ;
        RECT  64.692 7.632 64.776 7.656 ;
    END
  END b[8]
  PIN b[90]
    DIRECTION OUTPUT ;
    USE SIGNAL ;
    PORT
      LAYER M4 ;
        RECT  64.692 22.416 64.776 22.44 ;
    END
  END b[90]
  PIN b[91]
    DIRECTION OUTPUT ;
    USE SIGNAL ;
    PORT
      LAYER M4 ;
        RECT  64.692 22.512 64.776 22.536 ;
    END
  END b[91]
  PIN b[92]
    DIRECTION OUTPUT ;
    USE SIGNAL ;
    PORT
      LAYER M4 ;
        RECT  64.692 22.608 64.776 22.632 ;
    END
  END b[92]
  PIN b[93]
    DIRECTION OUTPUT ;
    USE SIGNAL ;
    PORT
      LAYER M4 ;
        RECT  64.692 22.704 64.776 22.728 ;
    END
  END b[93]
  PIN b[94]
    DIRECTION OUTPUT ;
    USE SIGNAL ;
    PORT
      LAYER M4 ;
        RECT  64.692 22.8 64.776 22.824 ;
    END
  END b[94]
  PIN b[95]
    DIRECTION OUTPUT ;
    USE SIGNAL ;
    PORT
      LAYER M4 ;
        RECT  64.692 22.896 64.776 22.92 ;
    END
  END b[95]
  PIN b[96]
    DIRECTION OUTPUT ;
    USE SIGNAL ;
    PORT
      LAYER M4 ;
        RECT  64.692 22.992 64.776 23.016 ;
    END
  END b[96]
  PIN b[97]
    DIRECTION OUTPUT ;
    USE SIGNAL ;
    PORT
      LAYER M4 ;
        RECT  64.692 23.088 64.776 23.112 ;
    END
  END b[97]
  PIN b[98]
    DIRECTION OUTPUT ;
    USE SIGNAL ;
    PORT
      LAYER M4 ;
        RECT  64.692 23.184 64.776 23.208 ;
    END
  END b[98]
  PIN b[99]
    DIRECTION OUTPUT ;
    USE SIGNAL ;
    PORT
      LAYER M4 ;
        RECT  64.692 23.28 64.776 23.304 ;
    END
  END b[99]
  PIN b[9]
    DIRECTION OUTPUT ;
    USE SIGNAL ;
    PORT
      LAYER M4 ;
        RECT  64.692 7.728 64.776 7.752 ;
    END
  END b[9]
  PIN ck
    DIRECTION INPUT ;
    USE SIGNAL ;
    PORT
      LAYER M4 ;
        RECT  0 13.104 0.084 13.128 ;
    END
  END ck
  PIN ckf
    DIRECTION INPUT ;
    USE SIGNAL ;
    PORT
      LAYER M4 ;
        RECT  0 13.2 0.084 13.224 ;
    END
  END ckf
  PIN ea
    DIRECTION INPUT ;
    USE SIGNAL ;
    PORT
      LAYER M3 ;
        RECT  23.868 30.179 23.886 30.216 ;
    END
  END ea
  PIN fault
    DIRECTION OUTPUT ;
    USE SIGNAL ;
    PORT
      LAYER M4 ;
        RECT  0 13.296 0.084 13.32 ;
    END
  END fault
  PIN k0
    DIRECTION INPUT ;
    USE SIGNAL ;
    PORT
      LAYER M4 ;
        RECT  0 13.392 0.084 13.416 ;
    END
  END k0
  PIN k1
    DIRECTION INPUT ;
    USE SIGNAL ;
    PORT
      LAYER M4 ;
        RECT  0 13.488 0.084 13.512 ;
    END
  END k1
  PIN k2
    DIRECTION INPUT ;
    USE SIGNAL ;
    PORT
      LAYER M4 ;
        RECT  0 13.584 0.084 13.608 ;
    END
  END k2
  PIN rs
    DIRECTION INPUT ;
    USE SIGNAL ;
    PORT
      LAYER M4 ;
        RECT  0 13.68 0.084 13.704 ;
    END
  END rs
  PIN tie_hi
    DIRECTION OUTPUT ;
    USE SIGNAL ;
    PORT
      LAYER M4 ;
        RECT  0 13.776 0.084 13.8 ;
    END
  END tie_hi
  PIN tie_lo
    DIRECTION OUTPUT ;
    USE SIGNAL ;
    PORT
      LAYER M4 ;
        RECT  0 13.872 0.084 13.896 ;
    END
  END tie_lo
  PIN VDD
    DIRECTION INOUT ;
    USE POWER ;
    PORT
      LAYER M5 ;
        RECT  61.992 2.151 62.112 27.833 ;
        RECT  59.292 2.151 59.412 27.833 ;
        RECT  56.592 2.151 56.712 27.833 ;
        RECT  53.892 2.151 54.012 27.833 ;
        RECT  51.192 2.151 51.312 27.833 ;
        RECT  48.492 2.151 48.612 27.833 ;
        RECT  45.792 2.151 45.912 27.833 ;
        RECT  43.092 2.151 43.212 27.833 ;
        RECT  40.392 2.151 40.512 27.833 ;
        RECT  37.692 2.151 37.812 27.833 ;
        RECT  34.992 2.151 35.112 27.833 ;
        RECT  32.292 2.151 32.412 27.833 ;
        RECT  29.592 2.151 29.712 27.833 ;
        RECT  26.892 2.151 27.012 27.833 ;
        RECT  24.192 2.151 24.312 27.833 ;
        RECT  21.492 2.151 21.612 27.833 ;
        RECT  18.792 2.151 18.912 27.833 ;
        RECT  16.092 2.151 16.212 27.833 ;
        RECT  13.392 2.151 13.512 27.833 ;
        RECT  10.692 2.151 10.812 27.833 ;
        RECT  7.992 2.151 8.112 27.833 ;
        RECT  5.292 2.151 5.412 27.833 ;
        RECT  2.592 2.151 2.712 27.833 ;
    END
  END VDD
  PIN VSS
    DIRECTION INOUT ;
    USE GROUND ;
    PORT
      LAYER M5 ;
        RECT  61.8 2.137 61.92 27.819 ;
        RECT  59.1 2.137 59.22 27.819 ;
        RECT  56.4 2.137 56.52 27.819 ;
        RECT  53.7 2.137 53.82 27.819 ;
        RECT  51 2.137 51.12 27.819 ;
        RECT  48.3 2.137 48.42 27.819 ;
        RECT  45.6 2.137 45.72 27.819 ;
        RECT  42.9 2.137 43.02 27.819 ;
        RECT  40.2 2.137 40.32 27.819 ;
        RECT  37.5 2.137 37.62 27.819 ;
        RECT  34.8 2.137 34.92 27.819 ;
        RECT  32.1 2.137 32.22 27.819 ;
        RECT  29.4 2.137 29.52 27.819 ;
        RECT  26.7 2.137 26.82 27.819 ;
        RECT  24 2.137 24.12 27.819 ;
        RECT  21.3 2.137 21.42 27.819 ;
        RECT  18.6 2.137 18.72 27.819 ;
        RECT  15.9 2.137 16.02 27.819 ;
        RECT  13.2 2.137 13.32 27.819 ;
        RECT  10.5 2.137 10.62 27.819 ;
        RECT  7.8 2.137 7.92 27.819 ;
        RECT  5.1 2.137 5.22 27.819 ;
        RECT  2.4 2.137 2.52 27.819 ;
    END
  END VSS
  OBS
    LAYER RVTN ;
     RECT  2.16 2.16 62.586 2.295 ;
     RECT  2.16 2.565 62.586 2.835 ;
     RECT  2.16 3.105 62.586 3.375 ;
     RECT  2.16 3.645 62.586 3.915 ;
     RECT  2.16 4.185 62.586 4.455 ;
     RECT  2.16 4.725 62.586 4.995 ;
     RECT  2.16 5.265 62.586 5.535 ;
     RECT  2.16 5.805 62.586 6.075 ;
     RECT  2.16 6.345 62.586 6.615 ;
     RECT  2.16 6.885 62.586 7.155 ;
     RECT  2.16 7.425 62.586 7.695 ;
     RECT  2.16 7.965 62.586 8.235 ;
     RECT  2.16 8.505 62.586 8.775 ;
     RECT  2.16 9.045 62.586 9.315 ;
     RECT  2.16 9.585 62.586 9.855 ;
     RECT  2.16 10.125 62.586 10.395 ;
     RECT  2.16 10.665 62.586 10.935 ;
     RECT  2.16 11.205 62.586 11.475 ;
     RECT  2.16 11.745 62.586 12.015 ;
     RECT  2.16 12.285 62.586 12.555 ;
     RECT  2.16 12.825 62.586 13.095 ;
     RECT  2.16 13.365 62.586 13.635 ;
     RECT  2.16 13.905 62.586 14.175 ;
     RECT  2.16 14.445 62.586 14.715 ;
     RECT  2.16 14.985 62.586 15.255 ;
     RECT  2.16 15.525 62.586 15.795 ;
     RECT  2.16 16.065 62.586 16.335 ;
     RECT  2.16 16.605 62.586 16.875 ;
     RECT  2.16 17.145 62.586 17.415 ;
     RECT  2.16 17.685 62.586 17.955 ;
     RECT  2.16 18.225 62.586 18.495 ;
     RECT  2.16 18.765 62.586 19.035 ;
     RECT  2.16 19.305 62.586 19.575 ;
     RECT  2.16 19.845 62.586 20.115 ;
     RECT  2.16 20.385 62.586 20.655 ;
     RECT  2.16 20.925 62.586 21.195 ;
     RECT  2.16 21.465 62.586 21.735 ;
     RECT  2.16 22.005 62.586 22.275 ;
     RECT  2.16 22.545 62.586 22.815 ;
     RECT  2.16 23.085 62.586 23.355 ;
     RECT  2.16 23.625 62.586 23.895 ;
     RECT  2.16 24.165 62.586 24.435 ;
     RECT  2.16 24.705 62.586 24.975 ;
     RECT  2.16 25.245 62.586 25.515 ;
     RECT  2.16 25.785 62.586 26.055 ;
     RECT  2.16 26.325 62.586 26.595 ;
     RECT  2.16 26.865 62.586 27.135 ;
     RECT  2.16 27.405 62.586 27.675 ;
    LAYER RVTP ;
     RECT  2.16 2.295 62.586 2.565 ;
     RECT  2.16 2.835 62.586 3.105 ;
     RECT  2.16 3.375 62.586 3.645 ;
     RECT  2.16 3.915 62.586 4.185 ;
     RECT  2.16 4.455 62.586 4.725 ;
     RECT  2.16 4.995 62.586 5.265 ;
     RECT  2.16 5.535 62.586 5.805 ;
     RECT  2.16 6.075 62.586 6.345 ;
     RECT  2.16 6.615 62.586 6.885 ;
     RECT  2.16 7.155 62.586 7.425 ;
     RECT  2.16 7.695 62.586 7.965 ;
     RECT  2.16 8.235 62.586 8.505 ;
     RECT  2.16 8.775 62.586 9.045 ;
     RECT  2.16 9.315 62.586 9.585 ;
     RECT  2.16 9.855 62.586 10.125 ;
     RECT  2.16 10.395 62.586 10.665 ;
     RECT  2.16 10.935 62.586 11.205 ;
     RECT  2.16 11.475 62.586 11.745 ;
     RECT  2.16 12.015 62.586 12.285 ;
     RECT  2.16 12.555 62.586 12.825 ;
     RECT  2.16 13.095 62.586 13.365 ;
     RECT  2.16 13.635 62.586 13.905 ;
     RECT  2.16 14.175 62.586 14.445 ;
     RECT  2.16 14.715 62.586 14.985 ;
     RECT  2.16 15.255 62.586 15.525 ;
     RECT  2.16 15.795 62.586 16.065 ;
     RECT  2.16 16.335 62.586 16.605 ;
     RECT  2.16 16.875 62.586 17.145 ;
     RECT  2.16 17.415 62.586 17.685 ;
     RECT  2.16 17.955 62.586 18.225 ;
     RECT  2.16 18.495 62.586 18.765 ;
     RECT  2.16 19.035 62.586 19.305 ;
     RECT  2.16 19.575 62.586 19.845 ;
     RECT  2.16 20.115 62.586 20.385 ;
     RECT  2.16 20.655 62.586 20.925 ;
     RECT  2.16 21.195 62.586 21.465 ;
     RECT  2.16 21.735 62.586 22.005 ;
     RECT  2.16 22.275 62.586 22.545 ;
     RECT  2.16 22.815 62.586 23.085 ;
     RECT  2.16 23.355 62.586 23.625 ;
     RECT  2.16 23.895 62.586 24.165 ;
     RECT  2.16 24.435 62.586 24.705 ;
     RECT  2.16 24.975 62.586 25.245 ;
     RECT  2.16 25.515 62.586 25.785 ;
     RECT  2.16 26.055 62.586 26.325 ;
     RECT  2.16 26.595 62.586 26.865 ;
     RECT  2.16 27.135 62.586 27.405 ;
     RECT  2.16 27.675 62.586 27.81 ;
    LAYER M1 ;
     RECT  2.16 2.151 62.586 27.819 ;
    LAYER M2 ;
     RECT  0.139 14.112 2.16 14.13 ;
     RECT  0.103 14.886 2.16 14.904 ;
     RECT  2.16 2.151 20.911 27.819 ;
     RECT  20.911 2.151 22.235 27.864 ;
     RECT  22.235 2.151 23.071 27.819 ;
     RECT  23.935 29.574 23.971 29.592 ;
     RECT  23.971 29.574 24.035 30.024 ;
     RECT  24.035 30.006 24.079 30.024 ;
     RECT  24.079 30.006 24.467 30.168 ;
     RECT  24.467 30.006 24.899 30.024 ;
     RECT  25.879 30.006 25.979 30.024 ;
     RECT  23.071 2.151 29.903 27.936 ;
     RECT  29.903 2.151 30.335 27.9 ;
     RECT  30.335 2.151 31.523 27.864 ;
     RECT  36.175 30.15 36.455 30.168 ;
     RECT  31.523 2.151 37.255 27.819 ;
     RECT  37.255 2.151 37.543 27.864 ;
     RECT  37.291 30.15 37.967 30.168 ;
     RECT  36.031 29.34 38.191 29.358 ;
     RECT  38.191 29.34 38.291 30.024 ;
     RECT  37.543 2.151 40.019 27.936 ;
     RECT  40.019 2.151 40.999 27.9 ;
     RECT  42.043 30.15 42.179 30.168 ;
     RECT  38.291 29.34 43.367 29.358 ;
     RECT  40.999 2.151 46.751 27.936 ;
     RECT  46.751 2.151 48.875 27.864 ;
     RECT  48.875 2.151 62.586 27.819 ;
     RECT  62.586 19.512 62.843 26.658 ;
     RECT  62.586 5.85 63.311 13.824 ;
     RECT  62.843 19.512 63.311 26.514 ;
     RECT  63.311 7.776 63.347 8.964 ;
     RECT  63.311 9.756 63.347 13.824 ;
     RECT  63.311 19.746 63.347 23.454 ;
     RECT  63.311 25.416 63.347 26.424 ;
     RECT  63.347 7.866 63.383 7.884 ;
     RECT  63.347 8.712 63.383 8.964 ;
     RECT  63.347 12.762 63.383 13.662 ;
     RECT  63.383 12.996 63.419 13.662 ;
     RECT  63.383 8.946 63.887 8.964 ;
     RECT  63.347 10.44 63.887 11.808 ;
     RECT  63.347 19.746 63.887 22.266 ;
     RECT  63.311 24.516 63.887 24.534 ;
     RECT  63.347 25.524 63.887 26.424 ;
     RECT  63.887 11.214 63.923 11.232 ;
     RECT  63.887 20.394 63.923 20.412 ;
     RECT  63.887 21.204 63.923 22.068 ;
     RECT  63.347 23.13 63.923 23.454 ;
     RECT  63.887 25.866 63.923 26.424 ;
     RECT  63.311 5.85 63.959 6.804 ;
     RECT  63.419 13.302 63.959 13.662 ;
     RECT  63.923 21.321 63.959 21.339 ;
     RECT  63.923 23.436 63.959 23.454 ;
     RECT  63.923 25.866 63.959 25.884 ;
     RECT  63.959 13.644 63.995 13.662 ;
     RECT  63.959 5.85 64.679 6.264 ;
     RECT  64.615 7.506 64.715 7.524 ;
     RECT  64.679 6.246 64.751 6.264 ;
     RECT  64.651 8.28 64.751 8.298 ;
    LAYER M3 ;
     RECT  2.415 2.143 2.505 2.413 ;
     RECT  5.115 2.143 5.205 2.413 ;
     RECT  7.815 2.143 7.905 2.413 ;
     RECT  10.515 2.143 10.605 2.413 ;
     RECT  13.215 2.143 13.305 2.413 ;
     RECT  15.915 2.143 16.005 2.413 ;
     RECT  18.615 2.143 18.705 2.413 ;
     RECT  21.315 2.143 21.405 2.413 ;
     RECT  24.015 2.143 24.105 2.413 ;
     RECT  26.715 2.143 26.805 2.413 ;
     RECT  29.415 2.143 29.505 2.413 ;
     RECT  32.115 2.143 32.205 2.413 ;
     RECT  34.815 2.143 34.905 2.413 ;
     RECT  37.515 2.143 37.605 2.413 ;
     RECT  40.215 2.143 40.305 2.413 ;
     RECT  42.915 2.143 43.005 2.413 ;
     RECT  45.615 2.143 45.705 2.413 ;
     RECT  48.315 2.143 48.405 2.413 ;
     RECT  51.015 2.143 51.105 2.413 ;
     RECT  53.715 2.143 53.805 2.413 ;
     RECT  56.415 2.143 56.505 2.413 ;
     RECT  59.115 2.143 59.205 2.413 ;
     RECT  61.815 2.143 61.905 2.413 ;
     RECT  55.44 4.891 55.458 4.963 ;
     RECT  54.72 4.963 55.458 5.035 ;
     RECT  56.415 2.413 56.697 5.035 ;
     RECT  51.015 2.413 51.297 5.305 ;
     RECT  52.272 5.269 52.29 5.305 ;
     RECT  40.215 2.413 40.497 5.341 ;
     RECT  42.915 2.413 43.197 5.341 ;
     RECT  48.315 2.413 48.597 5.467 ;
     RECT  53.715 2.413 53.997 5.467 ;
     RECT  54.72 5.035 56.697 5.467 ;
     RECT  48.315 5.467 49.446 5.575 ;
     RECT  51.015 5.305 52.29 5.575 ;
     RECT  40.215 5.341 41.382 5.611 ;
     RECT  42.192 5.341 43.197 5.611 ;
     RECT  51.015 5.575 52.578 5.611 ;
     RECT  53.715 5.467 56.697 5.611 ;
     RECT  37.515 2.413 37.797 5.701 ;
     RECT  48.204 5.575 50.094 5.701 ;
     RECT  51.015 5.611 56.697 5.701 ;
     RECT  37.332 5.701 37.797 5.737 ;
     RECT  40.215 5.611 43.197 5.737 ;
     RECT  45.615 2.413 45.897 5.737 ;
     RECT  37.116 5.737 37.797 5.773 ;
     RECT  39.636 5.737 43.197 5.773 ;
     RECT  32.115 2.413 32.397 5.809 ;
     RECT  29.415 2.413 29.697 5.845 ;
     RECT  59.115 2.413 59.397 5.845 ;
     RECT  61.815 2.413 62.097 5.845 ;
     RECT  32.115 5.809 33.102 5.881 ;
     RECT  61.416 5.845 62.097 5.881 ;
     RECT  28.836 5.845 29.697 5.971 ;
     RECT  36.756 5.773 37.797 5.971 ;
     RECT  34.815 2.413 35.097 5.995 ;
     RECT  36.324 5.971 37.797 5.995 ;
     RECT  47.196 5.971 47.214 6.007 ;
     RECT  48.204 5.701 56.697 6.007 ;
     RECT  58.14 5.881 58.158 6.007 ;
     RECT  59.115 5.845 59.49 6.007 ;
     RECT  63.288 6.043 63.306 6.079 ;
     RECT  64.656 5.845 64.674 6.079 ;
     RECT  24.015 2.413 24.297 6.091 ;
     RECT  26.715 2.413 26.997 6.091 ;
     RECT  31.248 6.043 31.266 6.091 ;
     RECT  32.115 5.881 33.174 6.091 ;
     RECT  45.615 5.737 45.918 6.115 ;
     RECT  47.196 6.007 56.697 6.115 ;
     RECT  58.14 6.007 59.49 6.115 ;
     RECT  60.84 5.881 62.097 6.115 ;
     RECT  63.288 6.079 64.674 6.115 ;
     RECT  26.496 6.091 27.378 6.151 ;
     RECT  28.224 5.971 29.697 6.151 ;
     RECT  34.815 5.995 35.154 6.151 ;
     RECT  36.324 5.995 38.394 6.151 ;
     RECT  39.456 5.773 43.197 6.151 ;
     RECT  58.14 6.115 60.066 6.151 ;
     RECT  45 6.115 56.697 6.179 ;
     RECT  23.976 6.091 24.297 6.241 ;
     RECT  58.104 6.151 60.066 6.241 ;
     RECT  60.84 6.115 64.674 6.241 ;
     RECT  36.072 6.151 38.574 6.269 ;
     RECT  31.248 6.091 33.174 6.277 ;
     RECT  39.312 6.151 43.197 6.277 ;
     RECT  55.368 6.179 56.697 6.277 ;
     RECT  34.815 6.151 35.298 6.313 ;
     RECT  36.072 6.269 38.106 6.313 ;
     RECT  23.976 6.241 24.57 6.421 ;
     RECT  26.496 6.151 29.697 6.421 ;
     RECT  34.815 6.313 38.106 6.421 ;
     RECT  30.816 6.277 33.174 6.511 ;
     RECT  38.952 6.277 43.197 6.511 ;
     RECT  55.368 6.277 56.934 6.511 ;
     RECT  58.104 6.241 64.746 6.511 ;
     RECT  26.496 6.421 30.078 6.547 ;
     RECT  38.952 6.511 43.47 6.547 ;
     RECT  34.74 6.421 38.106 6.619 ;
     RECT  45 6.179 54.63 6.619 ;
     RECT  23.976 6.421 24.93 6.655 ;
     RECT  26.424 6.547 30.078 6.691 ;
     RECT  30.816 6.511 33.57 6.691 ;
     RECT  23.976 6.655 25.038 6.781 ;
     RECT  26.424 6.691 33.57 6.781 ;
     RECT  38.952 6.547 44.046 6.811 ;
     RECT  44.928 6.619 54.63 6.811 ;
     RECT  34.596 6.619 38.106 6.889 ;
     RECT  26.424 6.781 33.75 6.925 ;
     RECT  38.952 6.811 54.63 6.925 ;
     RECT  55.368 6.511 64.746 6.925 ;
     RECT  26.1 6.925 33.75 6.961 ;
     RECT  34.56 6.889 38.106 6.961 ;
     RECT  23.94 6.781 25.038 7.051 ;
     RECT  26.1 6.961 38.106 7.051 ;
     RECT  23.94 7.051 38.106 7.123 ;
     RECT  23.256 7.123 38.106 7.187 ;
     RECT  28.872 7.187 38.106 7.195 ;
     RECT  38.952 6.925 64.746 7.195 ;
     RECT  23.256 7.187 28.062 7.231 ;
     RECT  23.148 7.231 28.062 7.349 ;
     RECT  28.872 7.195 64.746 7.565 ;
     RECT  28.872 7.565 63.918 7.763 ;
     RECT  31.248 7.763 63.918 7.853 ;
     RECT  31.248 7.853 63.378 7.925 ;
     RECT  23.256 7.349 28.062 7.969 ;
     RECT  28.872 7.763 30.222 7.969 ;
     RECT  23.256 7.969 30.222 7.997 ;
     RECT  64.656 7.565 64.746 8.303 ;
     RECT  64.656 8.303 64.674 8.333 ;
     RECT  23.58 7.997 30.042 8.735 ;
     RECT  31.356 7.925 63.378 8.941 ;
     RECT  24.015 8.735 30.042 8.977 ;
     RECT  31.356 8.941 63.882 8.977 ;
     RECT  24.015 8.977 63.882 9.005 ;
     RECT  24.015 9.005 46.602 9.149 ;
     RECT  47.376 9.005 63.882 9.293 ;
     RECT  24.015 9.149 46.53 9.518 ;
     RECT  47.376 9.293 63.378 10.027 ;
     RECT  47.376 10.027 63.882 10.093 ;
     RECT  47.304 10.093 63.882 10.129 ;
     RECT  47.232 10.129 63.882 10.349 ;
     RECT  47.232 10.349 62.91 10.427 ;
     RECT  24.015 9.518 46.494 10.541 ;
     RECT  44.028 10.541 46.494 10.597 ;
     RECT  47.232 10.427 48.798 10.597 ;
     RECT  49.932 10.427 62.91 11.179 ;
     RECT  63.756 10.349 63.882 11.179 ;
     RECT  49.932 11.179 63.882 11.209 ;
     RECT  49.932 11.209 63.918 11.309 ;
     RECT  24.015 10.541 43.197 11.407 ;
     RECT  44.028 10.597 48.798 11.419 ;
     RECT  44.028 11.419 49.122 11.515 ;
     RECT  49.932 11.309 63.882 11.515 ;
     RECT  44.028 11.515 63.882 11.705 ;
     RECT  24.015 11.407 43.254 11.821 ;
     RECT  44.028 11.705 60.462 11.821 ;
     RECT  24.015 11.821 60.462 12.515 ;
     RECT  55.872 12.515 60.462 12.523 ;
     RECT  61.524 11.705 63.882 12.631 ;
     RECT  61.488 12.631 63.882 12.715 ;
     RECT  55.872 12.523 60.714 12.721 ;
     RECT  61.488 12.715 63.918 12.721 ;
     RECT  55.872 12.721 63.918 12.811 ;
     RECT  24.015 12.515 54.954 12.899 ;
     RECT  55.872 12.811 63.954 12.907 ;
     RECT  36.216 12.899 54.954 13.261 ;
     RECT  2.415 2.413 2.697 13.291 ;
     RECT  36.216 13.261 55.026 13.297 ;
     RECT  2.304 13.291 2.697 13.369 ;
     RECT  36.216 13.297 55.098 13.369 ;
     RECT  55.872 12.907 63.99 13.369 ;
     RECT  2.268 13.369 2.697 13.405 ;
     RECT  36.216 13.369 63.99 13.433 ;
     RECT  24.015 12.899 35.442 13.469 ;
     RECT  2.268 13.405 2.862 13.517 ;
     RECT  2.376 13.517 2.862 13.559 ;
     RECT  62.82 13.433 63.99 13.559 ;
     RECT  0.108 13.387 0.126 13.579 ;
     RECT  6.84 13.567 6.858 13.667 ;
     RECT  63.324 13.559 63.99 13.667 ;
     RECT  22.392 13.441 23.094 13.711 ;
     RECT  24.015 13.469 27.954 13.711 ;
     RECT  28.728 13.469 35.442 13.711 ;
     RECT  36.216 13.433 62.097 13.711 ;
     RECT  2.376 13.559 2.697 13.829 ;
     RECT  63.324 13.667 63.342 13.829 ;
     RECT  21.315 2.413 21.597 13.837 ;
     RECT  22.392 13.711 27.954 13.837 ;
     RECT  17.532 13.675 17.55 13.981 ;
     RECT  18.615 2.413 18.897 13.981 ;
     RECT  28.728 13.711 62.097 14.099 ;
     RECT  0.108 13.579 0.162 14.135 ;
     RECT  28.764 14.099 62.097 14.135 ;
     RECT  28.764 14.135 35.55 14.243 ;
     RECT  17.532 13.981 18.897 14.251 ;
     RECT  21.315 13.837 27.954 14.251 ;
     RECT  17.532 14.251 18.954 14.377 ;
     RECT  19.692 14.251 19.818 14.377 ;
     RECT  20.952 14.251 27.954 14.377 ;
     RECT  17.532 14.377 27.954 14.491 ;
     RECT  36.504 14.135 62.097 14.675 ;
     RECT  17.46 14.491 27.954 14.711 ;
     RECT  18.036 14.711 27.954 14.747 ;
     RECT  59.04 14.675 62.097 14.765 ;
     RECT  18.288 14.747 27.954 14.783 ;
     RECT  0.108 14.135 0.126 14.909 ;
     RECT  28.764 14.243 35.478 15.025 ;
     RECT  36.504 14.675 58.302 15.025 ;
     RECT  28.764 15.025 58.302 15.053 ;
     RECT  30.672 15.053 58.302 15.245 ;
     RECT  12.168 15.061 12.186 15.251 ;
     RECT  28.764 15.053 29.898 15.755 ;
     RECT  29.016 15.755 29.898 15.835 ;
     RECT  30.672 15.245 51.894 15.835 ;
     RECT  18.615 14.783 27.954 15.871 ;
     RECT  59.076 14.765 62.097 16.141 ;
     RECT  29.016 15.835 51.894 16.231 ;
     RECT  52.776 15.245 58.302 16.231 ;
     RECT  29.016 16.231 58.302 16.645 ;
     RECT  59.04 16.141 62.097 16.645 ;
     RECT  18.615 15.871 28.206 16.681 ;
     RECT  29.016 16.645 62.097 16.681 ;
     RECT  18.615 16.681 62.097 16.709 ;
     RECT  52.38 16.709 62.097 17.455 ;
     RECT  52.308 17.455 62.097 17.491 ;
     RECT  18.615 16.709 51.534 17.581 ;
     RECT  52.308 17.491 62.442 17.581 ;
     RECT  18.615 17.581 62.442 17.915 ;
     RECT  55.296 17.915 62.442 18.149 ;
     RECT  18.615 17.915 54.558 18.221 ;
     RECT  55.296 18.149 62.097 18.491 ;
     RECT  19.944 18.221 54.558 18.527 ;
     RECT  20.232 18.527 54.558 18.563 ;
     RECT  20.232 18.563 20.25 18.689 ;
     RECT  21.204 18.563 54.558 18.715 ;
     RECT  55.296 18.491 60.678 18.715 ;
     RECT  21.204 18.715 60.678 19.139 ;
     RECT  61.815 18.491 62.097 19.579 ;
     RECT  61.416 19.579 62.097 19.615 ;
     RECT  21.315 19.139 60.678 19.651 ;
     RECT  61.416 19.615 62.19 19.651 ;
     RECT  63.288 19.507 63.306 19.651 ;
     RECT  21.315 19.651 63.306 19.741 ;
     RECT  21.315 19.741 63.882 19.769 ;
     RECT  18.615 18.221 18.897 19.885 ;
     RECT  21.315 19.769 58.374 19.921 ;
     RECT  18.615 19.885 19.566 20.011 ;
     RECT  20.484 19.921 58.374 20.011 ;
     RECT  18.615 20.011 58.374 20.039 ;
     RECT  18.615 20.039 44.622 20.345 ;
     RECT  59.115 19.769 63.882 20.389 ;
     RECT  45.504 20.039 58.374 20.551 ;
     RECT  59.115 20.389 63.918 20.551 ;
     RECT  45.504 20.551 63.918 20.579 ;
     RECT  18.615 20.345 44.586 20.695 ;
     RECT  18.324 20.695 44.586 20.921 ;
     RECT  18.36 20.921 44.586 21.067 ;
     RECT  18.36 21.067 44.658 21.091 ;
     RECT  45.504 20.579 55.278 21.091 ;
     RECT  56.052 20.579 63.918 21.316 ;
     RECT  56.052 21.316 63.954 21.344 ;
     RECT  17.46 21.235 17.478 21.397 ;
     RECT  18.36 21.091 55.278 21.631 ;
     RECT  56.052 21.344 62.442 21.631 ;
     RECT  63.288 21.344 63.954 21.677 ;
     RECT  17.46 21.397 17.622 21.775 ;
     RECT  18.36 21.631 62.442 21.775 ;
     RECT  17.424 21.775 62.442 21.965 ;
     RECT  17.424 21.965 19.026 22.199 ;
     RECT  19.836 21.965 62.442 22.243 ;
     RECT  63.288 21.677 63.918 22.243 ;
     RECT  19.836 22.243 63.918 22.253 ;
     RECT  19.836 22.253 63.882 22.445 ;
     RECT  17.424 22.199 18.897 22.585 ;
     RECT  15.915 2.413 16.197 22.747 ;
     RECT  17.064 22.585 18.897 22.747 ;
     RECT  19.836 22.445 62.334 22.775 ;
     RECT  19.836 22.775 60.57 22.843 ;
     RECT  19.8 22.843 60.57 22.981 ;
     RECT  61.488 22.775 62.334 23.009 ;
     RECT  15.915 22.747 18.897 23.089 ;
     RECT  19.692 22.981 60.57 23.089 ;
     RECT  63.288 22.445 63.882 23.125 ;
     RECT  61.776 23.009 62.334 23.275 ;
     RECT  15.915 23.089 60.57 23.351 ;
     RECT  61.776 23.275 62.406 23.371 ;
     RECT  63.288 23.125 63.918 23.371 ;
     RECT  61.776 23.371 63.918 23.431 ;
     RECT  15.915 23.351 59.562 23.597 ;
     RECT  15.915 23.597 59.526 23.819 ;
     RECT  15.915 23.819 58.302 23.855 ;
     RECT  61.776 23.431 63.954 24.077 ;
     RECT  22.752 23.855 58.302 24.089 ;
     RECT  22.752 24.089 22.77 24.125 ;
     RECT  23.616 24.089 58.302 24.125 ;
     RECT  60.3 23.351 60.57 24.169 ;
     RECT  61.776 24.077 63.882 24.169 ;
     RECT  59.076 23.819 59.526 24.511 ;
     RECT  60.3 24.169 63.882 24.511 ;
     RECT  15.915 23.855 21.942 24.745 ;
     RECT  22.68 24.709 22.698 24.745 ;
     RECT  15.915 24.745 22.698 24.871 ;
     RECT  23.616 24.125 33.678 24.871 ;
     RECT  59.076 24.511 63.882 24.899 ;
     RECT  15.915 24.871 22.842 24.907 ;
     RECT  23.616 24.871 33.75 24.907 ;
     RECT  15.915 24.907 33.75 24.943 ;
     RECT  34.524 24.125 58.302 24.943 ;
     RECT  15.915 24.943 58.302 25.321 ;
     RECT  59.076 24.899 61.038 25.321 ;
     RECT  61.815 24.899 63.882 25.387 ;
     RECT  61.815 25.387 63.918 25.483 ;
     RECT  15.915 25.321 61.038 25.789 ;
     RECT  61.815 25.483 63.954 25.789 ;
     RECT  15.915 25.789 63.954 25.889 ;
     RECT  15.915 25.889 63.918 25.979 ;
     RECT  61.632 25.979 63.918 26.015 ;
     RECT  15.915 25.979 60.534 26.249 ;
     RECT  61.815 26.015 63.918 26.429 ;
     RECT  61.815 26.429 63.306 26.519 ;
     RECT  61.815 26.519 62.838 26.627 ;
     RECT  62.82 26.627 62.838 26.663 ;
     RECT  15.915 26.249 60.426 26.789 ;
     RECT  34.815 26.789 60.246 26.861 ;
     RECT  15.915 26.789 33.966 27.059 ;
     RECT  15.915 27.059 33.822 27.095 ;
     RECT  36.108 26.861 60.246 27.167 ;
     RECT  15.915 27.095 33.498 27.239 ;
     RECT  15.915 27.239 32.706 27.329 ;
     RECT  33.48 27.239 33.498 27.329 ;
     RECT  52.344 27.167 60.246 27.329 ;
     RECT  15.915 27.329 32.562 27.365 ;
     RECT  36.108 27.167 51.606 27.365 ;
     RECT  52.344 27.329 55.674 27.365 ;
     RECT  56.415 27.329 57.114 27.365 ;
     RECT  57.888 27.329 60.246 27.365 ;
     RECT  57.924 27.365 60.246 27.401 ;
     RECT  15.915 27.365 32.526 27.473 ;
     RECT  57.924 27.401 59.958 27.473 ;
     RECT  2.415 13.829 2.697 27.557 ;
     RECT  5.115 2.413 5.397 27.557 ;
     RECT  7.815 2.413 8.097 27.557 ;
     RECT  10.515 2.413 10.797 27.557 ;
     RECT  13.215 2.413 13.497 27.557 ;
     RECT  15.915 27.473 26.997 27.557 ;
     RECT  34.815 26.861 35.097 27.557 ;
     RECT  36.108 27.365 51.534 27.557 ;
     RECT  56.415 27.365 56.697 27.557 ;
     RECT  61.815 26.627 62.097 27.557 ;
     RECT  16.107 27.557 26.997 27.599 ;
     RECT  28.008 27.473 32.526 27.599 ;
     RECT  45.792 27.557 50.346 27.599 ;
     RECT  52.992 27.365 55.674 27.599 ;
     RECT  57.924 27.473 59.397 27.599 ;
     RECT  17.712 27.599 26.997 27.635 ;
     RECT  32.307 27.599 32.454 27.635 ;
     RECT  46.728 27.599 49.374 27.635 ;
     RECT  52.992 27.599 54.486 27.635 ;
     RECT  55.476 27.599 55.494 27.635 ;
     RECT  57.924 27.599 57.942 27.635 ;
     RECT  17.712 27.635 19.926 27.671 ;
     RECT  28.008 27.599 31.518 27.677 ;
     RECT  46.728 27.635 47.142 27.677 ;
     RECT  23.832 27.635 26.997 27.68 ;
     RECT  28.08 27.677 31.518 27.707 ;
     RECT  29.088 27.707 30.33 27.743 ;
     RECT  51.207 27.557 51.534 27.743 ;
     RECT  36.108 27.557 45.018 27.773 ;
     RECT  39.132 27.773 45.018 27.779 ;
     RECT  39.132 27.779 43.794 27.821 ;
     RECT  2.607 27.557 2.697 27.827 ;
     RECT  5.307 27.557 5.397 27.827 ;
     RECT  8.007 27.557 8.097 27.827 ;
     RECT  10.707 27.557 10.797 27.827 ;
     RECT  13.407 27.557 13.497 27.827 ;
     RECT  16.107 27.599 16.974 27.827 ;
     RECT  20.88 27.635 23.094 27.827 ;
     RECT  23.868 27.68 26.997 27.827 ;
     RECT  29.607 27.743 30.33 27.827 ;
     RECT  32.307 27.635 32.397 27.827 ;
     RECT  35.007 27.557 35.097 27.827 ;
     RECT  45.807 27.599 45.897 27.827 ;
     RECT  48.507 27.635 48.87 27.827 ;
     RECT  51.207 27.743 51.297 27.827 ;
     RECT  53.907 27.635 53.997 27.827 ;
     RECT  56.607 27.557 56.697 27.827 ;
     RECT  59.307 27.599 59.397 27.827 ;
     RECT  62.007 27.557 62.097 27.827 ;
     RECT  20.88 27.827 20.934 27.869 ;
     RECT  21.96 27.827 23.094 27.869 ;
     RECT  28.224 27.707 28.314 27.869 ;
     RECT  31.5 27.707 31.518 27.869 ;
     RECT  39.276 27.821 43.794 27.869 ;
     RECT  48.852 27.827 48.87 27.869 ;
     RECT  29.88 27.827 30.33 27.905 ;
     RECT  39.996 27.869 43.794 27.905 ;
     RECT  21.96 27.869 21.978 27.917 ;
     RECT  36.108 27.773 38.286 27.917 ;
     RECT  39.996 27.905 43.362 27.917 ;
     RECT  22.824 27.869 23.094 27.941 ;
     RECT  23.868 27.827 26.874 27.941 ;
     RECT  29.88 27.905 29.898 27.941 ;
     RECT  39.996 27.917 42.318 27.941 ;
     RECT  44.532 27.779 45.018 27.941 ;
     RECT  46.728 27.677 46.746 27.941 ;
     RECT  20.88 27.869 20.898 28.205 ;
     RECT  17.856 27.671 19.926 28.349 ;
     RECT  17.856 28.349 17.874 28.397 ;
     RECT  18.648 28.349 19.926 28.397 ;
     RECT  19.008 28.397 19.926 28.445 ;
     RECT  16.668 27.827 16.974 28.493 ;
     RECT  19.008 28.445 19.386 28.493 ;
     RECT  36.108 27.917 38.214 29.335 ;
     RECT  22.824 27.941 22.842 29.357 ;
     RECT  40.356 27.941 40.806 29.357 ;
     RECT  43.344 27.917 43.362 29.363 ;
     RECT  40.788 29.357 40.806 29.659 ;
     RECT  41.724 27.941 42.318 29.659 ;
     RECT  23.868 27.941 25.974 29.707 ;
     RECT  23.868 29.707 26.118 29.755 ;
     RECT  36.036 29.335 38.214 30.001 ;
     RECT  40.788 29.659 42.822 30.091 ;
     RECT  40.716 30.091 42.822 30.139 ;
     RECT  17.64 30.043 17.658 30.173 ;
     RECT  23.868 29.755 26.19 30.204 ;
     RECT  36.036 30.001 38.286 30.204 ;
     RECT  40.644 30.139 42.894 30.204 ;
    LAYER M4 ;
     RECT  0.181 16.608 0.325 16.632 ;
     RECT  0.06 13.104 0.371 13.896 ;
     RECT  0.371 13.296 2.408 13.896 ;
     RECT  0.325 16.08 2.408 16.632 ;
     RECT  2.408 2.148 2.512 27.552 ;
     RECT  2.512 2.418 2.6 27.552 ;
     RECT  2.6 2.418 2.704 27.822 ;
     RECT  2.704 13.68 5.108 13.704 ;
     RECT  2.704 16.08 5.108 16.632 ;
     RECT  5.108 2.148 5.212 27.552 ;
     RECT  5.212 2.418 5.3 27.552 ;
     RECT  5.3 2.418 5.404 27.822 ;
     RECT  5.404 13.68 7.808 13.704 ;
     RECT  5.404 16.08 7.808 16.632 ;
     RECT  7.808 2.148 7.912 27.552 ;
     RECT  7.912 2.418 8 27.552 ;
     RECT  8 2.418 8.104 27.822 ;
     RECT  8.104 13.68 10.508 13.704 ;
     RECT  8.104 16.08 10.508 16.632 ;
     RECT  10.508 2.148 10.612 27.552 ;
     RECT  10.612 2.418 10.7 27.552 ;
     RECT  10.7 2.418 10.804 27.822 ;
     RECT  10.804 13.68 13.208 13.704 ;
     RECT  10.804 16.08 13.208 16.632 ;
     RECT  13.208 2.148 13.312 27.552 ;
     RECT  13.312 2.418 13.4 27.552 ;
     RECT  13.4 2.418 13.504 27.822 ;
     RECT  13.504 13.68 15.908 13.704 ;
     RECT  13.504 16.08 15.908 16.632 ;
     RECT  15.908 2.148 16.012 27.552 ;
     RECT  16.012 2.418 16.1 27.552 ;
     RECT  16.1 2.418 16.204 27.822 ;
     RECT  16.453 28.32 16.549 28.344 ;
     RECT  16.549 28.32 16.613 28.44 ;
     RECT  16.613 28.32 16.837 28.488 ;
     RECT  16.837 28.32 16.885 29.352 ;
     RECT  16.204 26.208 16.972 27.336 ;
     RECT  16.972 27.312 17.221 27.336 ;
     RECT  16.885 28.32 17.221 30.072 ;
     RECT  16.204 13.68 17.449 13.704 ;
     RECT  17.449 13.68 17.561 14.52 ;
     RECT  16.204 24.48 17.629 24.504 ;
     RECT  17.221 27.312 17.629 30.072 ;
     RECT  16.972 26.208 17.989 26.232 ;
     RECT  17.629 27.312 17.989 30.168 ;
     RECT  17.485 22.704 18.061 22.728 ;
     RECT  17.989 26.208 18.385 30.168 ;
     RECT  17.629 24.48 18.493 24.696 ;
     RECT  18.385 25.728 18.493 30.168 ;
     RECT  17.561 14.496 18.608 14.52 ;
     RECT  16.204 16.08 18.608 16.632 ;
     RECT  18.061 22.704 18.608 23.304 ;
     RECT  18.493 24.48 18.608 30.168 ;
     RECT  18.608 2.148 18.712 30.168 ;
     RECT  18.712 2.418 18.904 30.168 ;
     RECT  18.904 24.672 19.037 30.168 ;
     RECT  19.037 25.536 19.937 30.168 ;
     RECT  18.904 22.848 20.225 23.688 ;
     RECT  18.904 20.496 20.365 20.52 ;
     RECT  18.904 14.448 20.725 14.952 ;
     RECT  18.904 15.984 20.725 16.632 ;
     RECT  19.937 25.536 20.909 28.2 ;
     RECT  20.365 20.496 21.049 20.904 ;
     RECT  19.937 29.328 21.107 30.168 ;
     RECT  21.049 20.496 21.157 21 ;
     RECT  20.725 14.448 21.308 16.632 ;
     RECT  19.933 18.192 21.308 18.216 ;
     RECT  21.157 20.4 21.308 21 ;
     RECT  20.225 22.848 21.308 22.872 ;
     RECT  20.909 25.536 21.308 27.912 ;
     RECT  21.308 2.148 21.412 27.912 ;
     RECT  21.412 2.418 21.604 27.912 ;
     RECT  21.604 25.536 21.989 27.912 ;
     RECT  21.989 25.536 22.133 27.72 ;
     RECT  21.604 14.352 22.597 22.872 ;
     RECT  22.597 14.352 22.637 23.016 ;
     RECT  22.637 14.352 22.853 20.136 ;
     RECT  21.107 29.328 22.853 29.352 ;
     RECT  22.133 25.632 22.889 27.72 ;
     RECT  22.889 25.632 23.101 27.672 ;
     RECT  23.101 25.488 23.509 27.672 ;
     RECT  23.245 7.44 23.557 7.992 ;
     RECT  22.637 21.216 23.785 21.96 ;
     RECT  22.637 22.992 23.785 23.016 ;
     RECT  23.509 24.624 23.86 27.672 ;
     RECT  22.853 14.448 23.893 20.136 ;
     RECT  23.785 21.216 24.001 23.016 ;
     RECT  23.86 24.624 24.001 27.72 ;
     RECT  23.965 6.096 24.008 6.12 ;
     RECT  23.557 7.44 24.008 9.288 ;
     RECT  23.893 14.208 24.008 20.136 ;
     RECT  24.001 21.216 24.008 27.72 ;
     RECT  24.008 2.148 24.112 27.72 ;
     RECT  24.112 2.418 24.2 27.72 ;
     RECT  23.929 29.664 24.217 29.688 ;
     RECT  24.2 2.418 24.304 27.822 ;
     RECT  24.304 6.096 24.419 6.12 ;
     RECT  24.304 18.48 24.419 27.72 ;
     RECT  24.304 7.44 24.473 9.288 ;
     RECT  24.217 29.664 24.515 30.168 ;
     RECT  24.473 7.44 24.689 8.856 ;
     RECT  24.689 7.68 25.085 8.856 ;
     RECT  25.085 7.728 25.477 8.856 ;
     RECT  25.292 10.32 25.477 10.344 ;
     RECT  24.515 29.952 25.573 30.168 ;
     RECT  25.477 7.728 25.661 10.344 ;
     RECT  24.304 15.984 25.676 17.064 ;
     RECT  24.419 18.816 25.793 27.72 ;
     RECT  25.573 29.856 25.801 30.168 ;
     RECT  25.801 29.664 26.051 30.168 ;
     RECT  24.304 14.208 26.125 14.472 ;
     RECT  26.125 14.208 26.156 14.808 ;
     RECT  26.051 29.712 26.195 30.168 ;
     RECT  26.156 13.44 26.197 14.808 ;
     RECT  25.676 15.984 26.197 17.304 ;
     RECT  26.195 29.76 26.201 30.168 ;
     RECT  26.201 30.144 26.243 30.168 ;
     RECT  25.661 7.728 26.557 9.528 ;
     RECT  26.485 6.096 26.708 6.12 ;
     RECT  26.557 7.632 26.708 9.528 ;
     RECT  26.197 11.664 26.708 11.688 ;
     RECT  26.197 13.44 26.708 17.304 ;
     RECT  25.793 18.768 26.708 27.72 ;
     RECT  26.708 2.148 26.812 27.72 ;
     RECT  26.812 2.418 26.9 27.72 ;
     RECT  26.9 2.418 27.004 27.822 ;
     RECT  27.004 18.096 27.209 22.008 ;
     RECT  27.004 14.208 27.317 16.632 ;
     RECT  27.004 6.096 27.389 6.12 ;
     RECT  27.004 23.328 27.641 27.384 ;
     RECT  27.641 25.728 27.997 27.384 ;
     RECT  27.641 23.328 28.076 24.696 ;
     RECT  27.209 20.976 28.117 22.008 ;
     RECT  27.004 11.232 28.249 11.688 ;
     RECT  27.004 7.632 28.429 9.96 ;
     RECT  27.209 18.096 28.465 19.944 ;
     RECT  28.117 20.976 28.465 22.2 ;
     RECT  28.465 18.096 28.609 22.2 ;
     RECT  28.076 23.28 28.609 24.696 ;
     RECT  28.429 6.816 28.717 9.96 ;
     RECT  28.717 6.288 28.753 9.96 ;
     RECT  28.249 10.944 28.753 11.688 ;
     RECT  28.609 18.096 28.825 24.696 ;
     RECT  27.997 25.728 29.005 27.672 ;
     RECT  28.837 13.008 29.221 13.032 ;
     RECT  27.317 14.208 29.221 14.472 ;
     RECT  28.753 6.288 29.408 11.688 ;
     RECT  29.221 13.008 29.408 14.472 ;
     RECT  27.317 16.08 29.408 16.632 ;
     RECT  28.825 18 29.408 24.696 ;
     RECT  29.005 25.68 29.408 27.672 ;
     RECT  29.408 2.148 29.512 27.672 ;
     RECT  29.512 2.418 29.6 27.672 ;
     RECT  29.6 2.418 29.704 27.822 ;
     RECT  29.704 21.216 29.729 27.384 ;
     RECT  29.704 6.624 29.801 9.816 ;
     RECT  29.704 13.008 29.801 14.472 ;
     RECT  29.704 17.76 30.017 20.184 ;
     RECT  29.729 23.136 30.089 27.384 ;
     RECT  30.089 25.776 30.233 27.384 ;
     RECT  30.017 17.76 30.269 19.896 ;
     RECT  29.801 13.008 30.769 14.376 ;
     RECT  29.801 6.624 30.805 9.624 ;
     RECT  29.704 16.08 30.805 16.632 ;
     RECT  29.704 10.848 30.989 11.448 ;
     RECT  30.805 6.432 31.093 9.624 ;
     RECT  29.729 21.216 31.093 22.056 ;
     RECT  30.089 23.136 31.093 24.696 ;
     RECT  30.769 13.008 31.133 14.472 ;
     RECT  31.093 6.432 31.237 10.44 ;
     RECT  31.093 21.216 31.285 24.696 ;
     RECT  30.233 25.776 31.285 26.904 ;
     RECT  30.805 15.504 31.345 16.632 ;
     RECT  31.345 15.456 31.489 16.632 ;
     RECT  31.133 14.112 31.813 14.472 ;
     RECT  31.489 15.456 31.813 16.872 ;
     RECT  31.813 14.112 31.82 16.872 ;
     RECT  31.237 6.048 32.108 10.44 ;
     RECT  31.309 11.76 32.108 11.784 ;
     RECT  31.133 13.008 32.108 13.128 ;
     RECT  31.82 14.112 32.108 17.016 ;
     RECT  30.269 18.192 32.108 19.896 ;
     RECT  31.285 21.216 32.108 26.904 ;
     RECT  32.108 2.148 32.212 27.552 ;
     RECT  32.212 2.418 32.3 27.552 ;
     RECT  32.3 2.418 32.404 27.822 ;
     RECT  32.404 14.208 32.465 16.872 ;
     RECT  32.404 19.872 32.465 22.488 ;
     RECT  32.404 23.856 32.465 27.048 ;
     RECT  32.465 25.008 32.592 27.048 ;
     RECT  32.404 17.904 32.723 18.84 ;
     RECT  32.404 13.104 32.789 13.128 ;
     RECT  32.592 25.008 32.825 26.904 ;
     RECT  32.404 6.048 33.113 11.976 ;
     RECT  32.825 25.008 33.113 26.808 ;
     RECT  32.465 23.856 33.397 23.976 ;
     RECT  33.113 25.008 33.437 26.76 ;
     RECT  33.397 23.328 33.484 23.976 ;
     RECT  33.437 25.776 33.725 26.76 ;
     RECT  33.113 6.048 34.117 10.872 ;
     RECT  33.113 11.952 34.117 11.976 ;
     RECT  32.465 14.208 34.153 14.712 ;
     RECT  34.117 6.048 34.477 11.976 ;
     RECT  34.477 6.048 34.652 12.888 ;
     RECT  34.652 6.048 34.693 13.08 ;
     RECT  32.465 16.08 34.693 16.872 ;
     RECT  32.723 18.192 34.729 18.84 ;
     RECT  32.465 19.872 34.729 22.008 ;
     RECT  33.725 25.776 34.729 25.848 ;
     RECT  34.693 6.048 34.808 13.176 ;
     RECT  34.153 14.208 34.808 14.808 ;
     RECT  34.693 15.984 34.808 16.872 ;
     RECT  34.729 18.192 34.808 22.008 ;
     RECT  33.484 23.904 34.808 23.976 ;
     RECT  34.729 25.248 34.808 25.848 ;
     RECT  34.808 2.148 34.912 27.552 ;
     RECT  34.912 2.418 35 27.552 ;
     RECT  35 2.418 35.104 27.822 ;
     RECT  35.104 19.248 35.165 23.976 ;
     RECT  35.165 19.248 35.273 20.184 ;
     RECT  35.273 19.344 35.603 20.184 ;
     RECT  35.104 15.744 35.777 18.216 ;
     RECT  35.104 6 35.957 14.52 ;
     RECT  35.603 19.344 35.993 19.896 ;
     RECT  35.777 15.744 36.268 17.112 ;
     RECT  35.104 25.776 36.325 26.856 ;
     RECT  35.165 21.216 36.457 23.976 ;
     RECT  36.457 21.216 36.461 24.552 ;
     RECT  36.461 21.216 36.529 22.776 ;
     RECT  36.461 23.808 36.601 24.552 ;
     RECT  36.325 25.776 36.601 27.672 ;
     RECT  35.957 13.2 36.673 14.52 ;
     RECT  36.268 15.744 36.673 16.968 ;
     RECT  36.284 30.144 36.946 30.168 ;
     RECT  36.601 23.808 36.997 27.672 ;
     RECT  36.946 30.096 37.177 30.168 ;
     RECT  35.957 6 37.393 11.976 ;
     RECT  36.673 13.2 37.393 16.968 ;
     RECT  37.393 6 37.508 16.968 ;
     RECT  35.777 18.144 37.508 18.216 ;
     RECT  35.993 19.824 37.508 19.896 ;
     RECT  36.529 20.88 37.508 22.776 ;
     RECT  36.997 23.808 37.508 27.72 ;
     RECT  37.508 2.148 37.612 27.72 ;
     RECT  37.612 2.418 37.7 27.72 ;
     RECT  37.7 2.418 37.804 27.822 ;
     RECT  37.804 20.88 38.005 27.822 ;
     RECT  37.177 29.328 38.147 30.168 ;
     RECT  38.005 20.88 38.189 27.912 ;
     RECT  37.804 6 38.195 12.456 ;
     RECT  38.147 29.328 38.243 30.12 ;
     RECT  38.189 21.072 38.297 27.912 ;
     RECT  38.195 6 38.405 12.36 ;
     RECT  37.804 19.584 38.657 19.896 ;
     RECT  37.804 13.92 38.765 18.216 ;
     RECT  38.765 13.92 38.873 16.872 ;
     RECT  38.873 14.112 38.945 16.872 ;
     RECT  38.297 21.072 39.053 27.816 ;
     RECT  39.053 25.776 39.161 27.816 ;
     RECT  38.657 19.872 39.301 19.896 ;
     RECT  39.053 21.072 39.301 24.744 ;
     RECT  38.405 6.048 39.517 12.36 ;
     RECT  39.301 19.872 39.733 24.744 ;
     RECT  39.517 6.048 39.877 12.6 ;
     RECT  39.733 19.536 40.129 24.744 ;
     RECT  39.161 25.776 40.129 27.72 ;
     RECT  39.877 6 40.208 12.6 ;
     RECT  38.945 14.112 40.208 14.52 ;
     RECT  38.945 16.08 40.208 16.872 ;
     RECT  38.765 17.904 40.208 18.216 ;
     RECT  40.129 19.536 40.208 27.72 ;
     RECT  40.208 2.148 40.312 27.72 ;
     RECT  38.243 29.328 40.385 29.352 ;
     RECT  40.312 2.418 40.4 27.72 ;
     RECT  40.4 2.418 40.504 27.822 ;
     RECT  40.504 15.648 40.565 27.72 ;
     RECT  40.504 5.616 40.817 13.128 ;
     RECT  40.817 5.616 40.979 12.552 ;
     RECT  40.979 6 41.069 12.552 ;
     RECT  40.565 15.648 41.075 27.624 ;
     RECT  41.075 16.848 41.74 27.624 ;
     RECT  41.74 16.848 41.753 16.968 ;
     RECT  41.74 18.192 41.833 27.624 ;
     RECT  41.069 6.048 42.037 12.552 ;
     RECT  41.833 19.776 42.133 27.624 ;
     RECT  42.037 6.048 42.145 13.128 ;
     RECT  40.504 14.112 42.145 14.52 ;
     RECT  41.075 15.648 42.253 15.864 ;
     RECT  41.753 16.848 42.253 16.872 ;
     RECT  42.145 6.048 42.289 14.52 ;
     RECT  42.253 15.648 42.289 16.872 ;
     RECT  42.133 19.776 42.793 27.768 ;
     RECT  40.604 29.664 42.844 30.168 ;
     RECT  42.793 19.776 42.877 27.912 ;
     RECT  42.844 30.144 42.905 30.168 ;
     RECT  42.289 6.048 42.908 16.872 ;
     RECT  41.833 18.192 42.908 18.792 ;
     RECT  42.877 19.776 42.908 27.822 ;
     RECT  42.908 2.148 43.012 27.822 ;
     RECT  43.012 2.418 43.204 27.822 ;
     RECT  43.204 6.048 44.165 27.672 ;
     RECT  44.165 6.048 45.133 24.696 ;
     RECT  44.165 25.728 45.133 27.672 ;
     RECT  45.133 6.048 45.608 27.672 ;
     RECT  45.608 2.148 45.712 27.672 ;
     RECT  45.712 2.418 45.8 27.672 ;
     RECT  45.8 2.418 45.904 27.822 ;
     RECT  45.904 6.048 47.153 27.672 ;
     RECT  47.153 6.048 48.308 27.384 ;
     RECT  48.308 2.148 48.412 27.552 ;
     RECT  48.412 2.418 48.5 27.552 ;
     RECT  48.5 2.418 48.604 27.822 ;
     RECT  48.604 5.76 49.421 27.192 ;
     RECT  49.421 5.76 49.457 17.064 ;
     RECT  49.457 6 49.571 17.064 ;
     RECT  49.421 18.096 49.612 27.192 ;
     RECT  49.612 18.192 49.817 27.192 ;
     RECT  49.817 18.192 50.869 23.928 ;
     RECT  49.817 25.008 50.869 27.192 ;
     RECT  49.571 6 51.008 17.016 ;
     RECT  50.869 18.192 51.008 27.192 ;
     RECT  51.008 2.148 51.112 27.552 ;
     RECT  51.112 2.418 51.2 27.552 ;
     RECT  51.2 2.418 51.304 27.822 ;
     RECT  51.304 18 51.545 27.192 ;
     RECT  51.304 5.616 52.265 16.536 ;
     RECT  52.265 15.792 52.549 16.536 ;
     RECT  52.265 5.616 52.589 14.76 ;
     RECT  52.549 15.792 52.765 16.872 ;
     RECT  51.545 18 52.765 26.808 ;
     RECT  52.589 6 53.485 14.76 ;
     RECT  52.765 15.792 53.485 26.808 ;
     RECT  53.485 6 53.665 26.808 ;
     RECT  53.665 6 53.708 27.192 ;
     RECT  53.708 2.148 53.812 27.552 ;
     RECT  53.812 2.418 53.9 27.552 ;
     RECT  53.9 2.418 54.004 27.822 ;
     RECT  54.004 5.76 54.749 16.824 ;
     RECT  54.749 5.76 54.857 15.864 ;
     RECT  54.857 5.76 54.893 12.648 ;
     RECT  54.004 25.776 54.929 27.384 ;
     RECT  54.893 5.76 55.289 12.552 ;
     RECT  54.004 18 55.361 24.744 ;
     RECT  54.857 13.92 55.427 15.864 ;
     RECT  55.361 18.192 55.861 24.744 ;
     RECT  54.929 25.776 55.861 27.24 ;
     RECT  55.427 14.112 56.053 15.864 ;
     RECT  55.289 6.048 56.408 12.552 ;
     RECT  56.053 14.112 56.408 16.824 ;
     RECT  55.861 18.192 56.408 27.24 ;
     RECT  56.408 2.148 56.512 27.552 ;
     RECT  56.512 2.418 56.6 27.552 ;
     RECT  56.6 2.418 56.704 27.822 ;
     RECT  56.704 6.624 56.873 16.008 ;
     RECT  56.704 17.04 57.017 25.848 ;
     RECT  56.873 6.816 57.125 16.008 ;
     RECT  57.125 6.816 57.233 11.112 ;
     RECT  57.017 18.192 57.305 25.848 ;
     RECT  57.305 22.512 57.557 25.848 ;
     RECT  57.125 12.528 57.635 16.008 ;
     RECT  57.557 22.704 57.769 25.848 ;
     RECT  56.704 27.168 57.769 27.192 ;
     RECT  57.233 6.912 57.809 11.112 ;
     RECT  57.769 22.704 57.953 27.192 ;
     RECT  57.635 12.528 58.097 14.808 ;
     RECT  57.305 18.192 58.097 21.432 ;
     RECT  57.635 15.984 58.133 16.008 ;
     RECT  57.809 7.728 58.309 11.112 ;
     RECT  57.017 17.04 58.525 17.064 ;
     RECT  58.097 19.344 58.525 21.432 ;
     RECT  57.953 22.704 58.525 27.096 ;
     RECT  58.309 7.728 58.844 11.4 ;
     RECT  58.097 12.528 58.844 14.76 ;
     RECT  58.844 7.728 58.981 14.76 ;
     RECT  58.981 6.912 59.108 14.76 ;
     RECT  58.525 16.8 59.108 17.064 ;
     RECT  58.097 18.192 59.108 18.216 ;
     RECT  58.525 19.344 59.108 27.096 ;
     RECT  59.108 2.148 59.212 27.552 ;
     RECT  59.212 2.418 59.3 27.552 ;
     RECT  59.3 2.418 59.404 27.822 ;
     RECT  59.404 14.4 59.429 14.808 ;
     RECT  59.404 6.816 59.537 7.944 ;
     RECT  59.404 21.12 59.753 26.76 ;
     RECT  59.404 8.976 59.825 11.016 ;
     RECT  59.404 18.192 59.987 19.8 ;
     RECT  59.753 26.736 59.987 26.76 ;
     RECT  59.825 8.976 60.005 9.384 ;
     RECT  59.987 18.192 60.113 18.6 ;
     RECT  59.429 14.64 60.185 14.808 ;
     RECT  60.005 8.976 60.221 9 ;
     RECT  59.753 21.12 60.365 25.704 ;
     RECT  59.404 16.8 60.397 16.824 ;
     RECT  59.404 12.864 60.401 12.888 ;
     RECT  60.397 16.8 60.437 17.112 ;
     RECT  59.537 6.816 60.469 7.608 ;
     RECT  60.113 18.192 60.509 18.264 ;
     RECT  59.987 19.776 60.545 19.8 ;
     RECT  60.365 21.12 60.545 24.456 ;
     RECT  60.509 18.24 60.725 18.264 ;
     RECT  60.185 14.64 60.797 14.664 ;
     RECT  60.469 6.72 60.901 7.608 ;
     RECT  60.901 6.576 60.973 7.608 ;
     RECT  60.973 6.576 61.808 7.656 ;
     RECT  59.825 10.368 61.808 11.016 ;
     RECT  60.437 17.088 61.808 17.112 ;
     RECT  60.545 21.12 61.808 22.344 ;
     RECT  60.545 23.664 61.808 24.456 ;
     RECT  61.808 2.148 61.912 27.552 ;
     RECT  61.912 2.418 62 27.552 ;
     RECT  62 2.418 62.104 27.822 ;
     RECT  62.104 7.056 63.277 12.264 ;
     RECT  62.104 19.92 63.277 25.896 ;
     RECT  63.277 7.056 63.313 12.36 ;
     RECT  63.313 7.056 63.385 12.552 ;
     RECT  63.385 7.056 63.817 12.648 ;
     RECT  63.817 6.96 63.853 12.648 ;
     RECT  63.853 6.864 63.889 12.648 ;
     RECT  63.889 6.864 63.925 12.744 ;
     RECT  63.925 6.864 63.961 12.84 ;
     RECT  63.961 6.864 64.716 12.936 ;
     RECT  63.277 19.92 64.716 25.992 ;
     RECT  64.716 7.488 64.721 7.512 ;
    LAYER M5 ;
     RECT  2.4 2.137 2.52 2.151 ;
     RECT  5.1 2.137 5.22 2.151 ;
     RECT  7.8 2.137 7.92 2.151 ;
     RECT  10.5 2.137 10.62 2.151 ;
     RECT  13.2 2.137 13.32 2.151 ;
     RECT  15.9 2.137 16.02 2.151 ;
     RECT  18.6 2.137 18.72 2.151 ;
     RECT  21.3 2.137 21.42 2.151 ;
     RECT  24 2.137 24.12 2.151 ;
     RECT  26.7 2.137 26.82 2.151 ;
     RECT  29.4 2.137 29.52 2.151 ;
     RECT  32.1 2.137 32.22 2.151 ;
     RECT  34.8 2.137 34.92 2.151 ;
     RECT  37.5 2.137 37.62 2.151 ;
     RECT  40.2 2.137 40.32 2.151 ;
     RECT  42.9 2.137 43.02 2.151 ;
     RECT  45.6 2.137 45.72 2.151 ;
     RECT  48.3 2.137 48.42 2.151 ;
     RECT  51 2.137 51.12 2.151 ;
     RECT  53.7 2.137 53.82 2.151 ;
     RECT  56.4 2.137 56.52 2.151 ;
     RECT  59.1 2.137 59.22 2.151 ;
     RECT  61.8 2.137 61.92 2.151 ;
     RECT  40.2 2.151 40.512 5.605 ;
     RECT  51 2.151 51.312 5.605 ;
     RECT  34.8 2.151 35.112 5.989 ;
     RECT  24 2.151 24.312 6.085 ;
     RECT  45.6 2.151 45.912 6.277 ;
     RECT  51 5.605 51.672 6.563 ;
     RECT  48.3 2.151 48.612 6.661 ;
     RECT  29.4 2.151 29.712 6.805 ;
     RECT  34.8 5.989 35.592 6.805 ;
     RECT  42.9 2.151 43.212 6.805 ;
     RECT  48.3 6.661 49.176 6.805 ;
     RECT  56.4 2.151 56.712 6.805 ;
     RECT  59.1 2.151 59.412 6.805 ;
     RECT  59.1 6.805 60.312 6.901 ;
     RECT  40.2 5.605 40.968 6.947 ;
     RECT  53.7 2.151 54.012 7.045 ;
     RECT  48.3 6.805 49.56 7.333 ;
     RECT  51 6.563 51.312 7.333 ;
     RECT  33.936 6.805 35.592 7.381 ;
     RECT  37.5 2.151 37.812 7.381 ;
     RECT  42.192 6.805 43.212 7.381 ;
     RECT  24 6.085 24.408 7.475 ;
     RECT  41.76 7.381 43.212 7.475 ;
     RECT  33.936 7.381 35.736 7.619 ;
     RECT  58.992 6.901 60.312 7.619 ;
     RECT  44.976 6.277 45.912 7.621 ;
     RECT  56.4 6.805 56.952 7.669 ;
     RECT  52.992 7.045 54.012 7.715 ;
     RECT  58.992 7.619 59.412 7.763 ;
     RECT  56.4 7.669 57.048 7.909 ;
     RECT  40.2 6.947 40.632 7.955 ;
     RECT  24 7.475 24.312 7.957 ;
     RECT  42.9 7.475 43.212 7.957 ;
     RECT  44.64 7.621 45.912 7.957 ;
     RECT  48.3 7.333 51.312 8.051 ;
     RECT  41.76 7.475 41.784 8.437 ;
     RECT  42.9 7.957 45.912 8.437 ;
     RECT  48.3 8.051 49.272 8.437 ;
     RECT  37.2 7.381 37.812 8.483 ;
     RECT  25.344 8.389 25.368 8.485 ;
     RECT  34.8 7.619 35.736 8.915 ;
     RECT  23.568 7.957 24.312 9.299 ;
     RECT  41.76 8.437 45.912 9.301 ;
     RECT  33.552 8.341 33.576 9.347 ;
     RECT  41.616 9.301 45.912 9.347 ;
     RECT  47.76 8.437 49.272 9.347 ;
     RECT  56.4 7.909 57.336 9.349 ;
     RECT  37.5 8.483 37.812 9.637 ;
     RECT  41.616 9.347 41.784 10.067 ;
     RECT  42.9 9.347 45.912 10.307 ;
     RECT  55.824 9.349 57.336 10.307 ;
     RECT  25.344 8.485 25.56 10.355 ;
     RECT  29.28 6.805 29.712 10.355 ;
     RECT  36.768 9.637 37.812 10.499 ;
     RECT  45.6 10.307 45.912 10.933 ;
     RECT  34.8 8.915 35.496 10.981 ;
     RECT  59.1 7.763 59.412 11.077 ;
     RECT  56.4 10.307 57.336 11.123 ;
     RECT  37.5 10.499 37.812 11.413 ;
     RECT  45.6 10.933 46.008 11.459 ;
     RECT  56.4 11.123 56.808 11.459 ;
     RECT  25.536 10.355 25.56 11.653 ;
     RECT  26.7 2.151 27.012 11.653 ;
     RECT  28.32 11.269 28.344 11.653 ;
     RECT  29.4 10.355 29.712 11.653 ;
     RECT  28.32 11.653 29.712 11.699 ;
     RECT  42.9 10.307 44.472 11.795 ;
     RECT  34.176 10.981 35.496 11.987 ;
     RECT  34.8 11.987 35.496 11.989 ;
     RECT  40.2 7.955 40.512 12.277 ;
     RECT  37.5 11.413 38.184 12.467 ;
     RECT  41.76 10.067 41.784 12.517 ;
     RECT  42.9 11.795 44.28 12.517 ;
     RECT  53.7 7.715 54.012 12.517 ;
     RECT  55.392 12.469 55.416 12.517 ;
     RECT  53.7 12.517 55.416 12.659 ;
     RECT  41.76 12.517 44.28 12.755 ;
     RECT  48.3 9.347 49.272 12.757 ;
     RECT  32.1 2.151 32.412 12.997 ;
     RECT  28.848 11.699 29.712 13.043 ;
     RECT  34.8 11.989 35.592 13.045 ;
     RECT  40.2 12.277 40.632 13.139 ;
     RECT  34.704 13.045 35.592 13.187 ;
     RECT  0.336 13.093 0.36 13.189 ;
     RECT  58.8 11.077 59.412 13.429 ;
     RECT  47.328 12.757 49.272 13.859 ;
     RECT  55.392 12.659 55.416 13.955 ;
     RECT  40.2 13.139 40.512 14.101 ;
     RECT  41.76 12.755 43.848 14.101 ;
     RECT  31.344 12.997 32.412 14.147 ;
     RECT  52.368 13.573 52.392 14.243 ;
     RECT  53.7 12.659 54.12 14.243 ;
     RECT  25.536 11.653 27.012 14.245 ;
     RECT  56.4 11.459 56.712 14.245 ;
     RECT  58.464 13.429 59.412 14.245 ;
     RECT  21.3 2.151 21.612 14.341 ;
     RECT  56.4 14.245 59.412 14.435 ;
     RECT  21.3 14.341 21.72 14.483 ;
     RECT  48.3 13.859 49.272 14.483 ;
     RECT  45.6 11.459 45.912 14.533 ;
     RECT  45.6 14.533 46.728 14.723 ;
     RECT  21.3 14.483 21.612 14.773 ;
     RECT  34.8 13.187 35.592 14.773 ;
     RECT  56.4 14.435 57.624 15.395 ;
     RECT  56.4 15.395 56.808 15.541 ;
     RECT  20.784 14.773 21.612 16.019 ;
     RECT  34.704 14.773 35.592 16.019 ;
     RECT  0.192 13.189 0.36 16.115 ;
     RECT  40.2 14.101 43.848 16.259 ;
     RECT  34.8 16.019 35.592 16.357 ;
     RECT  29.4 13.043 29.712 16.501 ;
     RECT  31.872 14.147 32.412 16.501 ;
     RECT  41.76 16.259 43.848 16.547 ;
     RECT  0.192 16.115 0.216 16.643 ;
     RECT  52.704 16.501 52.728 16.789 ;
     RECT  53.7 14.243 54.012 16.789 ;
     RECT  52.704 16.789 54.012 16.835 ;
     RECT  56.064 15.541 56.808 16.835 ;
     RECT  48.3 14.483 48.612 16.837 ;
     RECT  50.4 8.051 51.312 16.837 ;
     RECT  37.5 12.467 37.812 17.029 ;
     RECT  24 9.299 24.312 17.077 ;
     RECT  34.8 16.357 36.216 17.123 ;
     RECT  47.232 16.501 47.256 17.171 ;
     RECT  25.344 14.245 27.012 17.315 ;
     RECT  40.2 16.259 40.632 17.411 ;
     RECT  41.76 16.547 43.608 17.605 ;
     RECT  52.848 16.835 54.012 17.891 ;
     RECT  31.872 16.501 32.712 17.939 ;
     RECT  37.5 17.029 38.232 17.939 ;
     RECT  23.184 17.077 24.312 17.987 ;
     RECT  29.28 16.501 29.712 18.035 ;
     RECT  48.3 16.837 51.312 18.131 ;
     RECT  53.7 17.891 54.012 18.133 ;
     RECT  24 17.987 24.312 18.469 ;
     RECT  25.344 17.315 25.368 18.469 ;
     RECT  58.8 14.435 59.412 18.565 ;
     RECT  40.2 17.411 40.512 18.613 ;
     RECT  41.664 17.605 43.608 18.613 ;
     RECT  24 18.469 25.368 18.757 ;
     RECT  26.7 17.315 27.012 18.757 ;
     RECT  31.872 17.939 32.412 18.947 ;
     RECT  53.7 18.133 54.312 18.949 ;
     RECT  50.4 18.131 51.312 18.995 ;
     RECT  29.4 18.035 29.712 19.141 ;
     RECT  21.3 16.019 21.612 19.237 ;
     RECT  53.232 18.949 54.312 19.237 ;
     RECT  56.4 16.835 56.808 19.427 ;
     RECT  58.8 18.565 59.976 19.523 ;
     RECT  53.04 19.237 54.312 20.003 ;
     RECT  34.8 17.123 35.352 20.149 ;
     RECT  53.04 20.003 54.012 20.339 ;
     RECT  21.3 19.237 21.72 20.389 ;
     RECT  21.168 20.389 21.72 20.867 ;
     RECT  29.28 19.141 29.712 21.013 ;
     RECT  53.232 20.339 54.012 21.109 ;
     RECT  48.3 18.131 49.416 21.155 ;
     RECT  28.896 21.013 29.712 21.301 ;
     RECT  32.1 18.947 32.412 21.637 ;
     RECT  48.3 21.155 48.612 21.781 ;
     RECT  28.896 21.301 30.264 22.021 ;
     RECT  53.232 21.109 54.456 22.021 ;
     RECT  53.232 22.021 55.272 22.069 ;
     RECT  56.4 19.427 56.712 22.069 ;
     RECT  28.656 22.021 30.264 22.165 ;
     RECT  31.968 21.637 32.412 22.165 ;
     RECT  53.232 22.069 56.712 22.259 ;
     RECT  55.92 22.259 56.712 22.501 ;
     RECT  21.3 20.867 21.72 22.693 ;
     RECT  55.92 22.501 56.904 22.693 ;
     RECT  58.992 19.523 59.976 22.739 ;
     RECT  40.2 18.613 43.608 22.741 ;
     RECT  45.6 14.723 45.912 22.789 ;
     RECT  47.328 21.781 48.612 22.835 ;
     RECT  53.232 22.259 54.456 23.027 ;
     RECT  24 18.757 27.012 23.317 ;
     RECT  28.128 22.165 30.264 23.317 ;
     RECT  40.2 22.741 43.896 23.317 ;
     RECT  48.3 22.835 48.612 23.317 ;
     RECT  24 23.317 30.264 23.411 ;
     RECT  55.92 22.693 57.624 23.507 ;
     RECT  45.6 22.789 46.008 23.603 ;
     RECT  33.408 23.317 33.432 23.987 ;
     RECT  34.8 20.149 35.592 23.987 ;
     RECT  40.08 23.317 43.896 24.227 ;
     RECT  53.232 23.027 54.012 24.563 ;
     RECT  24 23.411 29.712 24.613 ;
     RECT  51 18.995 51.312 24.613 ;
     RECT  18.6 2.151 18.912 24.661 ;
     RECT  59.1 22.739 59.976 24.661 ;
     RECT  55.92 23.507 56.904 24.709 ;
     RECT  58.704 24.661 59.976 24.709 ;
     RECT  55.92 24.709 59.976 24.947 ;
     RECT  37.5 17.939 37.812 25.141 ;
     RECT  55.92 24.947 56.712 25.235 ;
     RECT  36.816 25.141 37.812 25.285 ;
     RECT  31.296 22.165 32.412 25.331 ;
     RECT  18.192 24.661 18.912 25.525 ;
     RECT  21.3 22.693 22.104 25.621 ;
     RECT  23.52 24.613 29.712 25.621 ;
     RECT  57.792 24.947 59.976 25.667 ;
     RECT  48.3 23.317 49.56 25.763 ;
     RECT  40.2 24.227 43.896 26.051 ;
     RECT  58.128 25.667 59.976 26.099 ;
     RECT  50.88 24.613 51.312 26.149 ;
     RECT  36.816 25.285 38.424 26.197 ;
     RECT  21.3 25.621 29.712 26.243 ;
     RECT  40.2 26.051 43.8 26.291 ;
     RECT  15.9 2.151 16.212 26.389 ;
     RECT  32.1 25.331 32.412 26.533 ;
     RECT  45.6 23.603 45.912 26.629 ;
     RECT  48.3 25.763 48.612 26.629 ;
     RECT  59.1 26.099 59.976 26.771 ;
     RECT  21.3 26.243 27.012 26.819 ;
     RECT  28.176 26.243 29.712 26.819 ;
     RECT  40.2 26.291 43.416 26.819 ;
     RECT  50.688 26.149 51.312 26.819 ;
     RECT  32.1 26.533 32.52 27.059 ;
     RECT  21.3 26.819 22.776 27.203 ;
     RECT  55.296 26.677 55.32 27.203 ;
     RECT  18.192 25.525 19.176 27.253 ;
     RECT  15.9 26.389 16.92 27.301 ;
     RECT  29.088 26.819 29.712 27.347 ;
     RECT  36.816 26.197 39.144 27.395 ;
     RECT  45.6 26.629 46.008 27.395 ;
     RECT  47.76 26.629 48.612 27.395 ;
     RECT  15.9 27.301 17.16 27.397 ;
     RECT  18.192 27.253 19.464 27.397 ;
     RECT  36.816 27.395 38.28 27.443 ;
     RECT  21.3 27.203 22.632 27.539 ;
     RECT  22.608 27.539 22.632 27.587 ;
     RECT  36.816 27.443 38.232 27.637 ;
     RECT  21.3 27.539 21.612 27.733 ;
     RECT  2.4 2.151 2.712 27.819 ;
     RECT  5.1 2.151 5.412 27.819 ;
     RECT  7.8 2.151 8.112 27.819 ;
     RECT  10.5 2.151 10.812 27.819 ;
     RECT  13.2 2.151 13.512 27.819 ;
     RECT  15.9 27.397 19.464 27.819 ;
     RECT  24 26.819 27.012 27.819 ;
     RECT  29.4 27.347 29.712 27.819 ;
     RECT  32.1 27.059 32.412 27.819 ;
     RECT  34.8 23.987 35.112 27.819 ;
     RECT  40.2 26.819 43.212 27.819 ;
     RECT  45.6 27.395 45.912 27.819 ;
     RECT  48.3 27.395 48.612 27.819 ;
     RECT  51 26.819 51.312 27.819 ;
     RECT  53.7 24.563 54.012 27.819 ;
     RECT  56.4 25.235 56.712 27.819 ;
     RECT  59.1 26.771 59.412 27.819 ;
     RECT  61.8 2.151 62.112 27.819 ;
     RECT  2.592 27.819 2.712 27.833 ;
     RECT  5.292 27.819 5.412 27.833 ;
     RECT  7.992 27.819 8.112 27.833 ;
     RECT  10.692 27.819 10.812 27.833 ;
     RECT  13.392 27.819 13.512 27.833 ;
     RECT  16.092 27.819 19.464 27.833 ;
     RECT  20.976 27.733 21.612 27.833 ;
     RECT  24.192 27.819 27.012 27.833 ;
     RECT  29.592 27.819 29.712 27.833 ;
     RECT  32.292 27.819 32.412 27.833 ;
     RECT  34.992 27.819 35.112 27.833 ;
     RECT  40.392 27.819 43.212 27.833 ;
     RECT  45.792 27.819 45.912 27.833 ;
     RECT  48.492 27.819 48.612 27.833 ;
     RECT  51.192 27.819 51.312 27.833 ;
     RECT  53.892 27.819 54.012 27.833 ;
     RECT  56.592 27.819 56.712 27.833 ;
     RECT  59.292 27.819 59.412 27.833 ;
     RECT  61.992 27.819 62.112 27.833 ;
     RECT  36.336 27.637 38.232 29.843 ;
     RECT  20.976 27.833 21.096 30.131 ;
     RECT  38.112 29.843 38.232 30.131 ;
     RECT  16.464 27.833 19.464 30.16 ;
     RECT  21.072 30.131 21.096 30.179 ;
     RECT  24.384 27.833 26.232 30.179 ;
     RECT  36.336 29.843 37.128 30.179 ;
     RECT  38.112 30.131 38.136 30.179 ;
     RECT  40.656 27.833 42.84 30.179 ;
  END
END qfd_landh_128_NE_65x30
END LIBRARY
